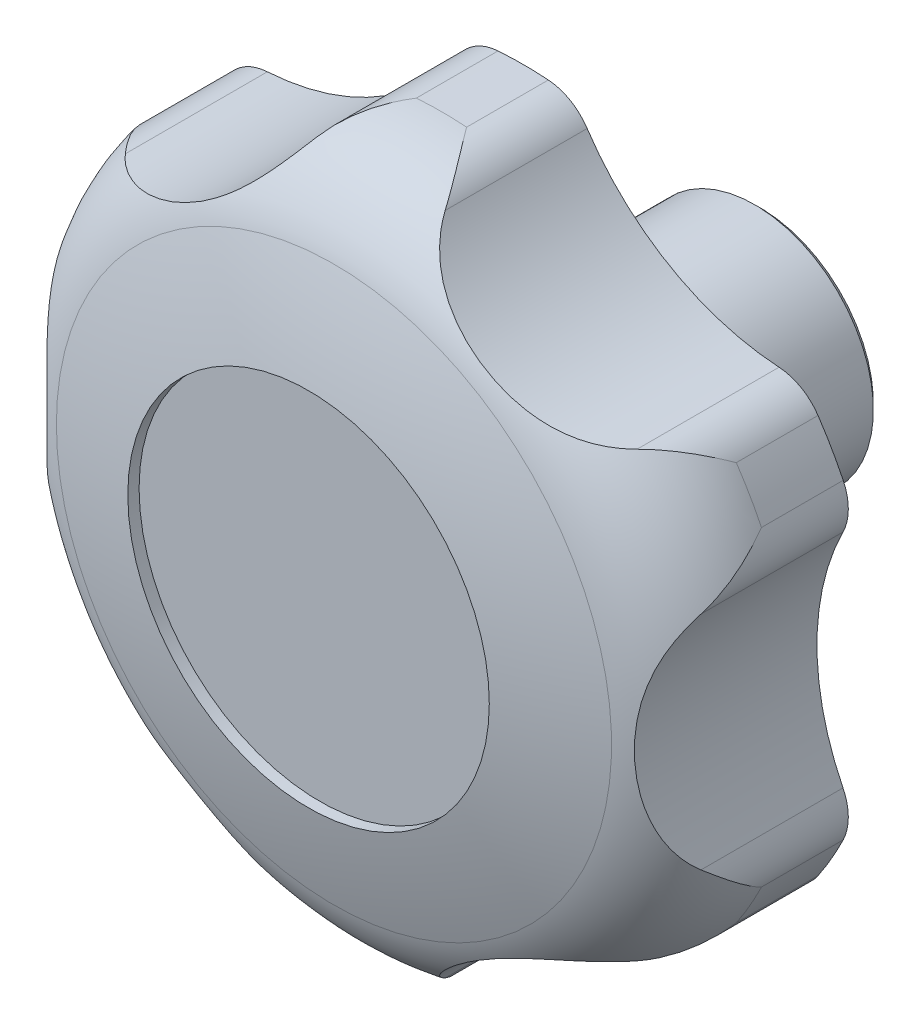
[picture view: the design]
ISO-10303-21;
HEADER;
FILE_DESCRIPTION(('STEP AP214'),'2;1');
FILE_NAME('part.step','',(''),(''),'','','');
FILE_SCHEMA(('AUTOMOTIVE_DESIGN { 1 0 10303 214 1 1 1 1 }'));
ENDSEC;
DATA;
#1=APPLICATION_CONTEXT('core data for automotive mechanical design processes');
#2=APPLICATION_PROTOCOL_DEFINITION('international standard','automotive_design',2000,#1);
#3=PRODUCT_CONTEXT('',#1,'mechanical');
#4=PRODUCT('Part','Part','',(#3));
#5=PRODUCT_RELATED_PRODUCT_CATEGORY('part','',(#4));
#6=PRODUCT_DEFINITION_FORMATION('','',#4);
#7=PRODUCT_DEFINITION_CONTEXT('part definition',#1,'design');
#8=PRODUCT_DEFINITION('design','',#6,#7);
#9=PRODUCT_DEFINITION_SHAPE('','',#8);
#10=(LENGTH_UNIT() NAMED_UNIT(*) SI_UNIT(.MILLI.,.METRE.));
#11=(NAMED_UNIT(*) PLANE_ANGLE_UNIT() SI_UNIT($,.RADIAN.));
#12=(NAMED_UNIT(*) SI_UNIT($,.STERADIAN.) SOLID_ANGLE_UNIT());
#13=UNCERTAINTY_MEASURE_WITH_UNIT(LENGTH_MEASURE(1.E-05),#10,'distance_accuracy_value','');
#14=(GEOMETRIC_REPRESENTATION_CONTEXT(3) GLOBAL_UNCERTAINTY_ASSIGNED_CONTEXT((#13)) GLOBAL_UNIT_ASSIGNED_CONTEXT((#10,
#11,#12)) REPRESENTATION_CONTEXT('',''));
#15=CARTESIAN_POINT('',(0.,0.,0.));
#16=DIRECTION('',(0.,0.,1.));
#17=DIRECTION('',(1.,0.,0.));
#18=AXIS2_PLACEMENT_3D('',#15,#16,#17);
#19=CARTESIAN_POINT('',(0.,0.,48.6287321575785));
#20=DIRECTION('',(0.,0.,1.));
#21=DIRECTION('',(-1.,0.,0.));
#22=AXIS2_PLACEMENT_3D('',#19,#20,#21);
#23=CYLINDRICAL_SURFACE('',#22,31.5);
#24=CARTESIAN_POINT('',(0.,0.,21.));
#25=DIRECTION('',(0.,0.,1.));
#26=DIRECTION('',(-1.,0.,0.));
#27=AXIS2_PLACEMENT_3D('',#24,#25,#26);
#28=CIRCLE('',#27,31.5);
#29=CARTESIAN_POINT('',(26.0979777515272,-17.639318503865,21.));
#30=VERTEX_POINT('',#29);
#31=CARTESIAN_POINT('',(28.3250868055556,-13.7818524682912,21.));
#32=VERTEX_POINT('',#31);
#33=EDGE_CURVE('E440',#30,#32,#28,.T.);
#34=ORIENTED_EDGE('',*,*,#33,.T.);
#35=DIRECTION('',(0.,0.,1.));
#36=VECTOR('',#35,1.);
#37=CARTESIAN_POINT('',(28.3250868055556,-13.7818524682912,0.));
#38=LINE('',#37,#36);
#39=CARTESIAN_POINT('',(28.3250868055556,-13.7818524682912,28.232767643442));
#40=VERTEX_POINT('',#39);
#41=EDGE_CURVE('E182',#32,#40,#38,.T.);
#42=ORIENTED_EDGE('',*,*,#41,.T.);
#43=CARTESIAN_POINT('',(0.,0.,28.232767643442));
#44=DIRECTION('',(0.,0.,1.));
#45=DIRECTION('',(-1.,0.,0.));
#46=AXIS2_PLACEMENT_3D('',#43,#44,#45);
#47=CIRCLE('',#46,31.5);
#48=CARTESIAN_POINT('',(26.0979777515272,-17.639318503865,28.232767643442));
#49=VERTEX_POINT('',#48);
#50=EDGE_CURVE('E197',#49,#40,#47,.T.);
#51=ORIENTED_EDGE('',*,*,#50,.F.);
#52=DIRECTION('',(0.,0.,1.));
#53=VECTOR('',#52,1.);
#54=CARTESIAN_POINT('',(26.0979777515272,-17.639318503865,0.));
#55=LINE('',#54,#53);
#56=EDGE_CURVE('E518',#30,#49,#55,.T.);
#57=ORIENTED_EDGE('',*,*,#56,.F.);
#58=EDGE_LOOP('',(#34,#42,#51,#57));
#59=FACE_BOUND('',#58,.T.);
#60=ADVANCED_FACE('F14',(#59),#23,.T.);
#61=CARTESIAN_POINT('',(-2.22710905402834,-31.421170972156,21.));
#62=VERTEX_POINT('',#61);
#63=CARTESIAN_POINT('',(2.22710905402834,-31.421170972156,21.));
#64=VERTEX_POINT('',#63);
#65=EDGE_CURVE('E443',#62,#64,#28,.T.);
#66=ORIENTED_EDGE('',*,*,#65,.T.);
#67=DIRECTION('',(0.,0.,1.));
#68=VECTOR('',#67,1.);
#69=CARTESIAN_POINT('',(2.22710905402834,-31.421170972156,0.));
#70=LINE('',#69,#68);
#71=CARTESIAN_POINT('',(2.22710905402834,-31.421170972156,28.232767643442));
#72=VERTEX_POINT('',#71);
#73=EDGE_CURVE('E524',#64,#72,#70,.T.);
#74=ORIENTED_EDGE('',*,*,#73,.T.);
#75=CARTESIAN_POINT('',(-2.22710905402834,-31.421170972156,28.232767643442));
#76=VERTEX_POINT('',#75);
#77=EDGE_CURVE('E454',#76,#72,#47,.T.);
#78=ORIENTED_EDGE('',*,*,#77,.F.);
#79=DIRECTION('',(0.,0.,1.));
#80=VECTOR('',#79,1.);
#81=CARTESIAN_POINT('',(-2.22710905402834,-31.421170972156,0.));
#82=LINE('',#81,#80);
#83=EDGE_CURVE('E527',#62,#76,#82,.T.);
#84=ORIENTED_EDGE('',*,*,#83,.F.);
#85=EDGE_LOOP('',(#66,#74,#78,#84));
#86=FACE_BOUND('',#85,.T.);
#87=ADVANCED_FACE('F406',(#86),#23,.T.);
#88=CARTESIAN_POINT('',(-28.3250868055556,-13.7818524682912,21.));
#89=VERTEX_POINT('',#88);
#90=CARTESIAN_POINT('',(-26.0979777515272,-17.639318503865,21.));
#91=VERTEX_POINT('',#90);
#92=EDGE_CURVE('E446',#89,#91,#28,.T.);
#93=ORIENTED_EDGE('',*,*,#92,.T.);
#94=DIRECTION('',(0.,0.,1.));
#95=VECTOR('',#94,1.);
#96=CARTESIAN_POINT('',(-26.0979777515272,-17.639318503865,0.));
#97=LINE('',#96,#95);
#98=CARTESIAN_POINT('',(-26.0979777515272,-17.639318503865,28.232767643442));
#99=VERTEX_POINT('',#98);
#100=EDGE_CURVE('E535',#91,#99,#97,.T.);
#101=ORIENTED_EDGE('',*,*,#100,.T.);
#102=CARTESIAN_POINT('',(-28.3250868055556,-13.7818524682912,28.232767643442));
#103=VERTEX_POINT('',#102);
#104=EDGE_CURVE('E450',#103,#99,#47,.T.);
#105=ORIENTED_EDGE('',*,*,#104,.F.);
#106=DIRECTION('',(0.,0.,1.));
#107=VECTOR('',#106,1.);
#108=CARTESIAN_POINT('',(-28.3250868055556,-13.7818524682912,0.));
#109=LINE('',#108,#107);
#110=EDGE_CURVE('E538',#89,#103,#109,.T.);
#111=ORIENTED_EDGE('',*,*,#110,.F.);
#112=EDGE_LOOP('',(#93,#101,#105,#111));
#113=FACE_BOUND('',#112,.T.);
#114=ADVANCED_FACE('F414',(#113),#23,.T.);
#115=CARTESIAN_POINT('',(-26.0979777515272,17.639318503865,21.));
#116=VERTEX_POINT('',#115);
#117=CARTESIAN_POINT('',(-28.3250868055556,13.7818524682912,21.));
#118=VERTEX_POINT('',#117);
#119=EDGE_CURVE('E445',#116,#118,#28,.T.);
#120=ORIENTED_EDGE('',*,*,#119,.T.);
#121=DIRECTION('',(0.,0.,1.));
#122=VECTOR('',#121,1.);
#123=CARTESIAN_POINT('',(-28.3250868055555,13.7818524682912,0.));
#124=LINE('',#123,#122);
#125=CARTESIAN_POINT('',(-28.3250868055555,13.7818524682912,28.232767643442));
#126=VERTEX_POINT('',#125);
#127=EDGE_CURVE('E37',#118,#126,#124,.T.);
#128=ORIENTED_EDGE('',*,*,#127,.T.);
#129=CARTESIAN_POINT('',(-26.0979777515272,17.639318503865,28.232767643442));
#130=VERTEX_POINT('',#129);
#131=EDGE_CURVE('E449',#130,#126,#47,.T.);
#132=ORIENTED_EDGE('',*,*,#131,.F.);
#133=DIRECTION('',(0.,0.,1.));
#134=VECTOR('',#133,1.);
#135=CARTESIAN_POINT('',(-26.0979777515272,17.639318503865,0.));
#136=LINE('',#135,#134);
#137=EDGE_CURVE('E547',#116,#130,#136,.T.);
#138=ORIENTED_EDGE('',*,*,#137,.F.);
#139=EDGE_LOOP('',(#120,#128,#132,#138));
#140=FACE_BOUND('',#139,.T.);
#141=ADVANCED_FACE('F427',(#140),#23,.T.);
#142=CARTESIAN_POINT('',(2.22710905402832,31.4211709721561,21.));
#143=VERTEX_POINT('',#142);
#144=CARTESIAN_POINT('',(-2.22710905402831,31.4211709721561,21.));
#145=VERTEX_POINT('',#144);
#146=EDGE_CURVE('E441',#143,#145,#28,.T.);
#147=ORIENTED_EDGE('',*,*,#146,.T.);
#148=DIRECTION('',(0.,0.,1.));
#149=VECTOR('',#148,1.);
#150=CARTESIAN_POINT('',(-2.22710905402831,31.4211709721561,0.));
#151=LINE('',#150,#149);
#152=CARTESIAN_POINT('',(-2.22710905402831,31.4211709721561,28.232767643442));
#153=VERTEX_POINT('',#152);
#154=EDGE_CURVE('E555',#145,#153,#151,.T.);
#155=ORIENTED_EDGE('',*,*,#154,.T.);
#156=CARTESIAN_POINT('',(2.22710905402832,31.4211709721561,28.232767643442));
#157=VERTEX_POINT('',#156);
#158=EDGE_CURVE('E571',#157,#153,#47,.T.);
#159=ORIENTED_EDGE('',*,*,#158,.F.);
#160=DIRECTION('',(0.,0.,1.));
#161=VECTOR('',#160,1.);
#162=CARTESIAN_POINT('',(2.22710905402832,31.4211709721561,0.));
#163=LINE('',#162,#161);
#164=EDGE_CURVE('E558',#143,#157,#163,.T.);
#165=ORIENTED_EDGE('',*,*,#164,.F.);
#166=EDGE_LOOP('',(#147,#155,#159,#165));
#167=FACE_BOUND('',#166,.T.);
#168=ADVANCED_FACE('F418',(#167),#23,.T.);
#169=CARTESIAN_POINT('',(28.3250868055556,13.7818524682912,21.));
#170=VERTEX_POINT('',#169);
#171=CARTESIAN_POINT('',(26.0979777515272,17.639318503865,21.));
#172=VERTEX_POINT('',#171);
#173=EDGE_CURVE('E433',#170,#172,#28,.T.);
#174=ORIENTED_EDGE('',*,*,#173,.T.);
#175=DIRECTION('',(0.,0.,1.));
#176=VECTOR('',#175,1.);
#177=CARTESIAN_POINT('',(26.0979777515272,17.639318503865,0.));
#178=LINE('',#177,#176);
#179=CARTESIAN_POINT('',(26.0979777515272,17.639318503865,28.232767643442));
#180=VERTEX_POINT('',#179);
#181=EDGE_CURVE('E435',#172,#180,#178,.T.);
#182=ORIENTED_EDGE('',*,*,#181,.T.);
#183=CARTESIAN_POINT('',(28.3250868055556,13.7818524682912,28.232767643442));
#184=VERTEX_POINT('',#183);
#185=EDGE_CURVE('E570',#184,#180,#47,.T.);
#186=ORIENTED_EDGE('',*,*,#185,.F.);
#187=DIRECTION('',(0.,0.,1.));
#188=VECTOR('',#187,1.);
#189=CARTESIAN_POINT('',(28.3250868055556,13.7818524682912,0.));
#190=LINE('',#189,#188);
#191=EDGE_CURVE('E437',#170,#184,#190,.T.);
#192=ORIENTED_EDGE('',*,*,#191,.F.);
#193=EDGE_LOOP('',(#174,#182,#186,#192));
#194=FACE_BOUND('',#193,.T.);
#195=ADVANCED_FACE('F408',(#194),#23,.T.);
#196=CARTESIAN_POINT('',(0.,0.,48.6287321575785));
#197=DIRECTION('',(0.,0.,1.));
#198=DIRECTION('',(-1.,0.,0.));
#199=AXIS2_PLACEMENT_3D('',#196,#197,#198);
#200=CYLINDRICAL_SURFACE('',#199,13.);
#201=CARTESIAN_POINT('',(0.,0.,21.));
#202=DIRECTION('',(0.,0.,1.));
#203=DIRECTION('',(-1.,0.,0.));
#204=AXIS2_PLACEMENT_3D('',#201,#202,#203);
#205=CIRCLE('',#204,13.);
#206=CARTESIAN_POINT('',(-13.,0.,21.));
#207=VERTEX_POINT('',#206);
#208=EDGE_CURVE('E469',#207,#207,#205,.T.);
#209=ORIENTED_EDGE('',*,*,#208,.F.);
#210=EDGE_LOOP('',(#209));
#211=FACE_BOUND('',#210,.T.);
#212=CARTESIAN_POINT('',(0.,0.,19.));
#213=DIRECTION('',(0.,0.,1.));
#214=DIRECTION('',(-1.,0.,0.));
#215=AXIS2_PLACEMENT_3D('',#212,#213,#214);
#216=CIRCLE('',#215,13.);
#217=CARTESIAN_POINT('',(-13.,0.,19.));
#218=VERTEX_POINT('',#217);
#219=EDGE_CURVE('E466',#218,#218,#216,.T.);
#220=ORIENTED_EDGE('',*,*,#219,.T.);
#221=EDGE_LOOP('',(#220));
#222=FACE_BOUND('',#221,.T.);
#223=ADVANCED_FACE('F16',(#211,#222),#200,.T.);
#224=CARTESIAN_POINT('',(0.,10.5,19.));
#225=DIRECTION('',(0.,0.,1.));
#226=DIRECTION('',(-1.,0.,0.));
#227=AXIS2_PLACEMENT_3D('',#224,#225,#226);
#228=PLANE('',#227);
#229=ORIENTED_EDGE('',*,*,#219,.F.);
#230=EDGE_LOOP('',(#229));
#231=FACE_BOUND('',#230,.T.);
#232=CARTESIAN_POINT('',(0.,0.,19.));
#233=DIRECTION('',(0.,0.,1.));
#234=DIRECTION('',(-1.,0.,0.));
#235=AXIS2_PLACEMENT_3D('',#232,#233,#234);
#236=CIRCLE('',#235,10.5);
#237=CARTESIAN_POINT('',(-10.5,0.,19.));
#238=VERTEX_POINT('',#237);
#239=EDGE_CURVE('E463',#238,#238,#236,.T.);
#240=ORIENTED_EDGE('',*,*,#239,.T.);
#241=EDGE_LOOP('',(#240));
#242=FACE_BOUND('',#241,.T.);
#243=ADVANCED_FACE('F425',(#231,#242),#228,.F.);
#244=CARTESIAN_POINT('',(0.,0.,48.6287321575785));
#245=DIRECTION('',(0.,0.,1.));
#246=DIRECTION('',(-1.,0.,0.));
#247=AXIS2_PLACEMENT_3D('',#244,#245,#246);
#248=CYLINDRICAL_SURFACE('',#247,10.5);
#249=CARTESIAN_POINT('',(0.,0.,0.5));
#250=DIRECTION('',(0.,0.,1.));
#251=DIRECTION('',(-1.,0.,0.));
#252=AXIS2_PLACEMENT_3D('',#249,#250,#251);
#253=CIRCLE('',#252,10.5);
#254=CARTESIAN_POINT('',(-10.5,0.,0.5));
#255=VERTEX_POINT('',#254);
#256=EDGE_CURVE('E460',#255,#255,#253,.T.);
#257=ORIENTED_EDGE('',*,*,#256,.T.);
#258=EDGE_LOOP('',(#257));
#259=FACE_BOUND('',#258,.T.);
#260=ORIENTED_EDGE('',*,*,#239,.F.);
#261=EDGE_LOOP('',(#260));
#262=FACE_BOUND('',#261,.T.);
#263=ADVANCED_FACE('F604',(#259,#262),#248,.T.);
#264=CARTESIAN_POINT('',(0.,0.,0.));
#265=DIRECTION('',(0.,0.,1.));
#266=DIRECTION('',(-1.,0.,0.));
#267=AXIS2_PLACEMENT_3D('',#264,#265,#266);
#268=CONICAL_SURFACE('',#267,10.,0.785398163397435);
#269=ORIENTED_EDGE('',*,*,#256,.F.);
#270=EDGE_LOOP('',(#269));
#271=FACE_BOUND('',#270,.T.);
#272=CARTESIAN_POINT('',(0.,0.,0.));
#273=DIRECTION('',(0.,0.,1.));
#274=DIRECTION('',(-1.,0.,0.));
#275=AXIS2_PLACEMENT_3D('',#272,#273,#274);
#276=CIRCLE('',#275,10.);
#277=CARTESIAN_POINT('',(-10.,0.,0.));
#278=VERTEX_POINT('',#277);
#279=EDGE_CURVE('E457',#278,#278,#276,.T.);
#280=ORIENTED_EDGE('',*,*,#279,.T.);
#281=EDGE_LOOP('',(#280));
#282=FACE_BOUND('',#281,.T.);
#283=ADVANCED_FACE('F598',(#271,#282),#268,.T.);
#284=CARTESIAN_POINT('',(0.,0.,0.));
#285=DIRECTION('',(0.,0.,1.));
#286=DIRECTION('',(-1.,0.,0.));
#287=AXIS2_PLACEMENT_3D('',#284,#285,#286);
#288=PLANE('',#287);
#289=ORIENTED_EDGE('',*,*,#279,.F.);
#290=EDGE_LOOP('',(#289));
#291=FACE_BOUND('',#290,.T.);
#292=ADVANCED_FACE('F591',(#291),#288,.F.);
#293=CARTESIAN_POINT('',(0.,0.,-38.3836717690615));
#294=DIRECTION('',(-1.,0.,0.));
#295=DIRECTION('',(0.,0.,-1.));
#296=AXIS2_PLACEMENT_3D('',#293,#294,#295);
#297=SPHERICAL_SURFACE('',#296,79.9999999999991);
#298=CARTESIAN_POINT('',(0.,0.,-38.3836717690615));
#299=DIRECTION('',(0.,0.,1.));
#300=DIRECTION('',(-1.,0.,0.));
#301=AXIS2_PLACEMENT_3D('',#298,#299,#300);
#302=SPHERICAL_SURFACE('',#301,79.9999999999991);
#303=CARTESIAN_POINT('',(0.,0.,37.7494018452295));
#304=DIRECTION('',(0.,0.,1.));
#305=DIRECTION('',(-1.,0.,0.));
#306=AXIS2_PLACEMENT_3D('',#303,#304,#305);
#307=CIRCLE('',#306,24.5714285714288);
#308=CARTESIAN_POINT('',(-24.5714285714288,0.,37.7494018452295));
#309=VERTEX_POINT('',#308);
#310=EDGE_CURVE('E453',#309,#309,#307,.T.);
#311=ORIENTED_EDGE('',*,*,#310,.T.);
#312=EDGE_LOOP('',(#311));
#313=FACE_BOUND('',#312,.T.);
#314=CARTESIAN_POINT('',(0.,0.,40.));
#315=DIRECTION('',(0.,0.,1.));
#316=DIRECTION('',(-1.,0.,0.));
#317=AXIS2_PLACEMENT_3D('',#314,#315,#316);
#318=CIRCLE('',#317,16.);
#319=CARTESIAN_POINT('',(-16.,0.,40.));
#320=VERTEX_POINT('',#319);
#321=EDGE_CURVE('E198',#320,#320,#318,.T.);
#322=ORIENTED_EDGE('',*,*,#321,.F.);
#323=EDGE_LOOP('',(#322));
#324=FACE_BOUND('',#323,.T.);
#325=ADVANCED_FACE('F589',(#313,#324),#302,.T.);
#326=CARTESIAN_POINT('',(0.,0.,28.232767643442));
#327=DIRECTION('',(0.,0.,1.));
#328=DIRECTION('',(-1.,0.,0.));
#329=AXIS2_PLACEMENT_3D('',#326,#327,#328);
#330=TOROIDAL_SURFACE('',#329,21.5,10.);
#331=CARTESIAN_POINT('',(26.0979777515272,-17.639318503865,28.232767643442));
#332=CARTESIAN_POINT('',(26.0957873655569,-17.6425592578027,28.2381661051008));
#333=CARTESIAN_POINT('',(26.0935927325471,-17.6457971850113,28.2435646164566));
#334=CARTESIAN_POINT('',(25.9715048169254,-17.8254189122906,28.5433082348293));
#335=CARTESIAN_POINT('',(25.8390070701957,-17.9933768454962,28.8377892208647));
#336=CARTESIAN_POINT('',(25.5505586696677,-18.3097082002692,29.4258443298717));
#337=CARTESIAN_POINT('',(25.3945993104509,-18.4580743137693,29.7194180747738));
#338=CARTESIAN_POINT('',(25.060613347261,-18.7326906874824,30.3051183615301));
#339=CARTESIAN_POINT('',(24.8825534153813,-18.8589068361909,30.5972420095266));
#340=CARTESIAN_POINT('',(24.5064415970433,-19.085843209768,31.1782260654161));
#341=CARTESIAN_POINT('',(24.3084021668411,-19.1865791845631,31.4670883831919));
#342=CARTESIAN_POINT('',(23.8777210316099,-19.3661170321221,32.0631220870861));
#343=CARTESIAN_POINT('',(23.643582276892,-19.4425638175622,32.3699417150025));
#344=CARTESIAN_POINT('',(23.2789979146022,-19.5283534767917,32.8243186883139));
#345=CARTESIAN_POINT('',(23.1553286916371,-19.5521302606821,32.9747024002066));
#346=CARTESIAN_POINT('',(22.9038337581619,-19.5894090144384,33.2733876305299));
#347=CARTESIAN_POINT('',(22.7760057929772,-19.6029053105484,33.4216879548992));
#348=CARTESIAN_POINT('',(22.6463394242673,-19.610904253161,33.5687610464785));
#349=B_SPLINE_CURVE_WITH_KNOTS('',3,(#331,#332,#333,#334,#335,#336,#337,#338,#339,#340,#341,
#342,#343,#344,#345,#346,#347,#348),.UNSPECIFIED.,.F.,.F.,(4,2,2,2,2,2,2,2,4),(0.,
0.0200000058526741,1.11045859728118,2.20132280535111,3.29385250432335,4.3857052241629,
5.56362960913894,6.15179569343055,6.74028614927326),.UNSPECIFIED.);
#350=CARTESIAN_POINT('',(22.6465394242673,-19.610891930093,33.568534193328));
#351=VERTEX_POINT('',#350);
#352=EDGE_CURVE('E199',#49,#351,#349,.T.);
#353=ORIENTED_EDGE('',*,*,#352,.F.);
#354=ORIENTED_EDGE('',*,*,#50,.T.);
#355=CARTESIAN_POINT('',(28.3067007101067,-9.8068324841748,33.568787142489));
#356=CARTESIAN_POINT('',(28.3508912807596,-9.89556849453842,33.4565618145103));
#357=CARTESIAN_POINT('',(28.3917729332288,-9.98498886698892,33.3436125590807));
#358=CARTESIAN_POINT('',(28.4670914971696,-10.1648549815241,33.1164224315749));
#359=CARTESIAN_POINT('',(28.5015295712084,-10.2553005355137,33.0021817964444));
#360=CARTESIAN_POINT('',(28.5953953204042,-10.5275208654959,32.6579333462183));
#361=CARTESIAN_POINT('',(28.6454651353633,-10.7103641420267,32.426166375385));
#362=CARTESIAN_POINT('',(28.721810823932,-11.076055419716,31.9595965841));
#363=CARTESIAN_POINT('',(28.7481337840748,-11.2589026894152,31.7248007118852));
#364=CARTESIAN_POINT('',(28.7783405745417,-11.622978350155,31.2525284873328));
#365=CARTESIAN_POINT('',(28.7822209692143,-11.804206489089,31.0150517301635));
#366=CARTESIAN_POINT('',(28.7634739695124,-12.2980890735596,30.3589883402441));
#367=CARTESIAN_POINT('',(28.7187582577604,-12.607264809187,29.9382841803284));
#368=CARTESIAN_POINT('',(28.5687108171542,-13.206004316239,29.0945771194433));
#369=CARTESIAN_POINT('',(28.4634632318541,-13.4955946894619,28.6715782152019));
#370=CARTESIAN_POINT('',(28.3285049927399,-13.7748156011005,28.2435645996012));
#371=CARTESIAN_POINT('',(28.3267981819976,-13.7783351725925,28.2381660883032));
#372=CARTESIAN_POINT('',(28.3250868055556,-13.7818524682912,28.232767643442));
#373=B_SPLINE_CURVE_WITH_KNOTS('',3,(#355,#356,#357,#358,#359,#360,#361,#362,#363,#364,#365,
#366,#367,#368,#369,#370,#371,#372),.UNSPECIFIED.,.F.,.F.,(4,2,2,2,2,2,2,2,4),(0.,
0.449123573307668,0.89816603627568,1.79532231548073,2.69069573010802,3.58620621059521,
5.15403517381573,6.71968999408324,6.73968999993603),.UNSPECIFIED.);
#374=CARTESIAN_POINT('',(28.3068003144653,-9.8070324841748,33.568534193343));
#375=VERTEX_POINT('',#374);
#376=EDGE_CURVE('E186',#375,#40,#373,.T.);
#377=ORIENTED_EDGE('',*,*,#376,.F.);
#378=CARTESIAN_POINT('',(28.306899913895,-9.80723248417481,33.568281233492));
#379=CARTESIAN_POINT('',(28.2673881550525,-9.72789258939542,33.6686385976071));
#380=CARTESIAN_POINT('',(28.227286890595,-9.64616596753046,33.7668454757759));
#381=CARTESIAN_POINT('',(28.1461835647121,-9.47811588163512,33.9588369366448));
#382=CARTESIAN_POINT('',(28.1051815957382,-9.39179288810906,34.0526219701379));
#383=CARTESIAN_POINT('',(27.9813412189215,-9.12640847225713,34.3269450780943));
#384=CARTESIAN_POINT('',(27.8975600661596,-8.94071625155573,34.5007229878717));
#385=CARTESIAN_POINT('',(27.7306770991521,-8.55559108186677,34.8277600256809));
#386=CARTESIAN_POINT('',(27.6475773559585,-8.35632234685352,34.9812149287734));
#387=CARTESIAN_POINT('',(27.4831867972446,-7.94415498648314,35.2697558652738));
#388=CARTESIAN_POINT('',(27.4018963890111,-7.73125333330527,35.4048377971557));
#389=CARTESIAN_POINT('',(27.2432790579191,-7.29467382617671,35.656528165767));
#390=CARTESIAN_POINT('',(27.1659377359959,-7.07104190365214,35.7732075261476));
#391=CARTESIAN_POINT('',(27.0164001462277,-6.61410095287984,35.9895642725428));
#392=CARTESIAN_POINT('',(26.9442035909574,-6.38079246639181,36.0892426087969));
#393=CARTESIAN_POINT('',(26.8060036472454,-5.90558258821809,36.2729593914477));
#394=CARTESIAN_POINT('',(26.7400171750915,-5.66366006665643,36.3569556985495));
#395=CARTESIAN_POINT('',(26.6154160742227,-5.173356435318,36.510259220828));
#396=CARTESIAN_POINT('',(26.5568025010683,-4.92497440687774,36.5795643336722));
#397=CARTESIAN_POINT('',(26.4181661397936,-4.28729101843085,36.738696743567));
#398=CARTESIAN_POINT('',(26.3437188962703,-3.89445767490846,36.8193385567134));
#399=CARTESIAN_POINT('',(26.2158958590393,-3.10074997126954,36.9533643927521));
#400=CARTESIAN_POINT('',(26.1625301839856,-2.69987184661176,37.006735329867));
#401=CARTESIAN_POINT('',(26.0777773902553,-1.89243908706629,37.0898241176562));
#402=CARTESIAN_POINT('',(26.0464425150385,-1.48587327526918,37.1194857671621));
#403=CARTESIAN_POINT('',(26.0064401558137,-0.670716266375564,37.1571359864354));
#404=CARTESIAN_POINT('',(25.9977694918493,-0.262125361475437,37.1651275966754));
#405=CARTESIAN_POINT('',(26.0032673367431,0.564334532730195,37.1600141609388));
#406=CARTESIAN_POINT('',(26.01797448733,0.982197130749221,37.146411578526));
#407=CARTESIAN_POINT('',(26.0710365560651,1.81513174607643,37.0960704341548));
#408=CARTESIAN_POINT('',(26.1093958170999,2.23020323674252,37.0593276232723));
#409=CARTESIAN_POINT('',(26.2090070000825,3.05355191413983,36.9600301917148));
#410=CARTESIAN_POINT('',(26.2702065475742,3.46184242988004,36.8975345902));
#411=CARTESIAN_POINT('',(26.4142334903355,4.26876333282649,36.7425858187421));
#412=CARTESIAN_POINT('',(26.4970492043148,4.66739881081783,36.6501488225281));
#413=CARTESIAN_POINT('',(26.65189721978,5.32280567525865,36.4661289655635));
#414=CARTESIAN_POINT('',(26.7186645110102,5.58351647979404,36.3840627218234));
#415=CARTESIAN_POINT('',(26.8599386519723,6.09659869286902,36.2024669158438));
#416=CARTESIAN_POINT('',(26.9344431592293,6.34897259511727,36.1029426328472));
#417=CARTESIAN_POINT('',(27.0896194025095,6.84271708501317,35.8852972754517));
#418=CARTESIAN_POINT('',(27.1702731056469,7.08411676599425,35.7672295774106));
#419=CARTESIAN_POINT('',(27.336207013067,7.55445583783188,35.5111726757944));
#420=CARTESIAN_POINT('',(27.4214863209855,7.78339762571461,35.3731873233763));
#421=CARTESIAN_POINT('',(27.5743147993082,8.17463300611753,35.1113840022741));
#422=CARTESIAN_POINT('',(27.6413411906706,8.33998254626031,34.9918111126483));
#423=CARTESIAN_POINT('',(27.7758194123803,8.66099232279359,34.7405668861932));
#424=CARTESIAN_POINT('',(27.8432711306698,8.81665500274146,34.6088986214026));
#425=CARTESIAN_POINT('',(27.9779423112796,9.11836971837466,34.3326466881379));
#426=CARTESIAN_POINT('',(28.0451570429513,9.26434887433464,34.1879809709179));
#427=CARTESIAN_POINT('',(28.177732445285,9.54473083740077,33.8868532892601));
#428=CARTESIAN_POINT('',(28.2430918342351,9.67912576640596,33.730383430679));
#429=CARTESIAN_POINT('',(28.306899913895,9.807232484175,33.5682812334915));
#430=B_SPLINE_CURVE_WITH_KNOTS('',3,(#378,#379,#380,#381,#382,#383,#384,#385,#386,#387,#388,
#389,#390,#391,#392,#393,#394,#395,#396,#397,#398,#399,#400,#401,#402,#403,#404,#405,#406,#407,
#408,#409,#410,#411,#412,#413,#414,#415,#416,#417,#418,#419,#420,#421,#422,#423,#424,#425,#426,
#427,#428,#429),.UNSPECIFIED.,.F.,.F.,(4,2,2,2,2,2,2,2,2,2,2,2,2,2,2,2,2,2,2,2,2,2,2,2,2,4),(0.,
0.401597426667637,0.803153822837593,1.60518118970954,2.39881165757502,3.19261900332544,
3.98328802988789,4.77391284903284,5.56663251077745,6.35946553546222,7.58127502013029,
8.8036702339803,10.028954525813,11.2540668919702,12.5078182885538,13.7617999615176,
15.0129236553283,16.2633726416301,17.106781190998,17.9499351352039,18.7907051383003,
19.6313127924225,20.2751395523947,20.9188032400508,21.5668619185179,22.2153579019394),.UNSPECIFIED.);
#431=CARTESIAN_POINT('',(28.3068003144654,9.80703248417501,33.5685341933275));
#432=VERTEX_POINT('',#431);
#433=EDGE_CURVE('E174',#375,#432,#430,.T.);
#434=ORIENTED_EDGE('',*,*,#433,.T.);
#435=CARTESIAN_POINT('',(28.3250868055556,13.7818524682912,28.232767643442));
#436=CARTESIAN_POINT('',(28.3267981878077,13.7783351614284,28.2381661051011));
#437=CARTESIAN_POINT('',(28.3285049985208,13.774815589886,28.2435646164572));
#438=CARTESIAN_POINT('',(28.4230180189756,13.5792734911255,28.5433082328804));
#439=CARTESIAN_POINT('',(28.5022249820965,13.3805481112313,28.8377892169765));
#440=CARTESIAN_POINT('',(28.6319517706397,12.9725787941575,29.4258443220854));
#441=CARTESIAN_POINT('',(28.6824609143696,12.7633309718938,29.7194180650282));
#442=CARTESIAN_POINT('',(28.7532926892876,12.3367824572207,30.3051183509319));
#443=CARTESIAN_POINT('',(28.7735691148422,12.1194699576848,30.5972420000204));
#444=CARTESIAN_POINT('',(28.7820458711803,11.6802793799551,31.1782260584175));
#445=CARTESIAN_POINT('',(28.7702660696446,11.4584042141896,31.467088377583));
#446=CARTESIAN_POINT('',(28.7104093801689,10.9956509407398,32.0631266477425));
#447=CARTESIAN_POINT('',(28.6595438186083,10.7546538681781,32.3699507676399));
#448=CARTESIAN_POINT('',(28.5515451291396,10.3960144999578,32.8243342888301));
#449=CARTESIAN_POINT('',(28.5103008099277,10.2770236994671,32.9747201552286));
#450=CARTESIAN_POINT('',(28.416835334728,10.0405799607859,33.2734096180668));
#451=CARTESIAN_POINT('',(28.3646081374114,9.92312790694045,33.4217120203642));
#452=CARTESIAN_POINT('',(28.3067007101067,9.80683248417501,33.568787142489));
#453=B_SPLINE_CURVE_WITH_KNOTS('',3,(#435,#436,#437,#438,#439,#440,#441,#442,#443,#444,#445,
#446,#447,#448,#449,#450,#451,#452),.UNSPECIFIED.,.F.,.F.,(4,2,2,2,2,2,2,2,4),(0.,
0.020000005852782,1.1104585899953,2.20132279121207,3.29385249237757,4.38570522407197,
5.56364696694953,6.15182175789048,6.74032093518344),.UNSPECIFIED.);
#454=EDGE_CURVE('E181',#184,#432,#453,.T.);
#455=ORIENTED_EDGE('',*,*,#454,.F.);
#456=ORIENTED_EDGE('',*,*,#185,.T.);
#457=CARTESIAN_POINT('',(22.6463394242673,19.610904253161,33.5687610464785));
#458=CARTESIAN_POINT('',(22.7452824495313,19.6048058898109,33.4565353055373));
#459=CARTESIAN_POINT('',(22.8431636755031,19.5954997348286,33.3435856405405));
#460=CARTESIAN_POINT('',(23.036591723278,19.5707934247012,33.11639470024));
#461=CARTESIAN_POINT('',(23.132138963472,19.5553943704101,33.0021536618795));
#462=CARTESIAN_POINT('',(23.4148216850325,19.5005727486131,32.6579040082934));
#463=CARTESIAN_POINT('',(23.5982035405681,19.4525117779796,32.4261362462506));
#464=CARTESIAN_POINT('',(23.953074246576,19.3357813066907,31.9595649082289));
#465=CARTESIAN_POINT('',(24.1245860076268,19.2671529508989,31.7247682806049));
#466=CARTESIAN_POINT('',(24.4549878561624,19.1112728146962,31.2524945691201));
#467=CARTESIAN_POINT('',(24.613876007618,19.0240181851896,31.015017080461));
#468=CARTESIAN_POINT('',(25.0322121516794,18.7608413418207,30.3589586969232));
#469=CARTESIAN_POINT('',(25.2776039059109,18.5675303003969,29.938260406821));
#470=CARTESIAN_POINT('',(25.7210962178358,18.138220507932,29.0945651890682));
#471=CARTESIAN_POINT('',(25.9192618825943,17.9022813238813,28.6715722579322));
#472=CARTESIAN_POINT('',(26.0935927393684,17.6457971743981,28.2435645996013));
#473=CARTESIAN_POINT('',(26.09578737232,17.6425592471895,28.2381660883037));
#474=CARTESIAN_POINT('',(26.0979777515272,17.639318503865,28.232767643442));
#475=B_SPLINE_CURVE_WITH_KNOTS('',3,(#457,#458,#459,#460,#461,#462,#463,#464,#465,#466,#467,
#468,#469,#470,#471,#472,#473,#474),.UNSPECIFIED.,.F.,.F.,(4,2,2,2,2,2,2,2,4),(0.,
0.449124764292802,0.898168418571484,1.79532709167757,2.6907028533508,3.58621567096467,
5.15402250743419,6.71965525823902,6.73965526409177),.UNSPECIFIED.);
#476=CARTESIAN_POINT('',(22.6465394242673,19.610891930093,33.5685341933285));
#477=VERTEX_POINT('',#476);
#478=EDGE_CURVE('E246',#477,#180,#475,.T.);
#479=ORIENTED_EDGE('',*,*,#478,.F.);
#480=CARTESIAN_POINT('',(22.6467394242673,19.6108796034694,33.568307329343));
#481=CARTESIAN_POINT('',(22.5582725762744,19.6163314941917,33.6686645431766));
#482=CARTESIAN_POINT('',(22.4674440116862,19.622466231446,33.7668712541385));
#483=CARTESIAN_POINT('',(22.2813555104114,19.6362540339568,33.9588623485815));
#484=CARTESIAN_POINT('',(22.1860960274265,19.6439069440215,34.0526471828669));
#485=CARTESIAN_POINT('',(21.8943444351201,19.6693507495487,34.3269696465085));
#486=CARTESIAN_POINT('',(21.6916385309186,19.689640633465,34.5007470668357));
#487=CARTESIAN_POINT('',(21.2746666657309,19.737679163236,34.8277830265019));
#488=CARTESIAN_POINT('',(21.0605439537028,19.7653474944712,34.9812373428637));
#489=CARTESIAN_POINT('',(20.6213992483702,19.8290657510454,35.2697770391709));
#490=CARTESIAN_POINT('',(20.396374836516,19.8651175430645,35.4048583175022));
#491=CARTESIAN_POINT('',(19.938975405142,19.9460417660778,35.6565473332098));
#492=CARTESIAN_POINT('',(19.7066329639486,19.990878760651,35.7732259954));
#493=CARTESIAN_POINT('',(19.2361400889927,20.089847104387,35.9895813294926));
#494=CARTESIAN_POINT('',(18.9979899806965,20.1439779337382,36.0892589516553));
#495=CARTESIAN_POINT('',(18.5173447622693,20.2618995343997,36.2729743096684));
#496=CARTESIAN_POINT('',(18.2748398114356,20.3257155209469,36.356969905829));
#497=CARTESIAN_POINT('',(17.7879226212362,20.4629610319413,36.5102720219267));
#498=CARTESIAN_POINT('',(17.5435101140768,20.5363919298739,36.5795764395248));
#499=CARTESIAN_POINT('',(16.9219401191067,20.7351730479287,36.7387072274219));
#500=CARTESIAN_POINT('',(16.5445116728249,20.8671178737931,36.8193480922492));
#501=CARTESIAN_POINT('',(15.7932269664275,21.1532765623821,36.9533720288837));
#502=CARTESIAN_POINT('',(15.4193725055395,21.3075010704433,37.0067420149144));
#503=CARTESIAN_POINT('',(14.6777370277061,21.6378224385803,37.0898288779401));
#504=CARTESIAN_POINT('',(14.3099724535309,21.8139701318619,37.1194895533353));
#505=CARTESIAN_POINT('',(13.5840231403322,22.1869088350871,37.1571377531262));
#506=CARTESIAN_POINT('',(13.2258370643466,22.3836969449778,37.1651283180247));
#507=CARTESIAN_POINT('',(12.5128497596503,22.8016915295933,37.1600126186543));
#508=CARTESIAN_POINT('',(12.1583233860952,23.0233612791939,37.146408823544));
#509=CARTESIAN_POINT('',(11.4635114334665,23.4857850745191,37.0960650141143));
#510=CARTESIAN_POINT('',(11.1232284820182,23.7265426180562,37.0593207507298));
#511=CARTESIAN_POINT('',(10.4599932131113,24.2244861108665,36.9600200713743));
#512=CARTESIAN_POINT('',(10.1370031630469,24.4816333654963,36.8975226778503));
#513=CARTESIAN_POINT('',(9.51020318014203,25.0098279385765,36.7425698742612));
#514=CARTESIAN_POINT('',(9.20638299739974,25.2808676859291,36.6501306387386));
#515=CARTESIAN_POINT('',(8.71621052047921,25.7426742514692,36.466107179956));
#516=CARTESIAN_POINT('',(8.52381391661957,25.9308511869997,36.384039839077));
#517=CARTESIAN_POINT('',(8.15011259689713,26.3097378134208,36.202441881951));
#518=CARTESIAN_POINT('',(7.96880455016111,26.5004467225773,36.1029165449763));
#519=CARTESIAN_POINT('',(7.6188011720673,26.8817036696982,35.8852691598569));
#520=CARTESIAN_POINT('',(7.45007162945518,27.072250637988,35.7672004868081));
#521=CARTESIAN_POINT('',(7.12571667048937,27.4511209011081,35.5111417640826));
#522=CARTESIAN_POINT('',(6.97008873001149,27.6394446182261,35.3731555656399));
#523=CARTESIAN_POINT('',(6.70768734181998,27.9674120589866,35.1113519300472));
#524=CARTESIAN_POINT('',(6.59800591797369,28.1081310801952,34.9917796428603));
#525=CARTESIAN_POINT('',(6.38724675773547,28.3850929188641,34.7405369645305));
#526=CARTESIAN_POINT('',(6.28616684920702,28.521336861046,34.6088696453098));
#527=CARTESIAN_POINT('',(6.09221377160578,28.7888183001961,34.3326200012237));
#528=CARTESIAN_POINT('',(5.99940134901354,28.9200152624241,34.1879556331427));
#529=CARTESIAN_POINT('',(5.82287463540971,29.1750154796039,33.886831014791));
#530=CARTESIAN_POINT('',(5.73916652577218,29.2988136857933,33.7303628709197));
#531=CARTESIAN_POINT('',(5.66012837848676,29.4181244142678,33.5682625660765));
#532=B_SPLINE_CURVE_WITH_KNOTS('',3,(#480,#481,#482,#483,#484,#485,#486,#487,#488,#489,#490,
#491,#492,#493,#494,#495,#496,#497,#498,#499,#500,#501,#502,#503,#504,#505,#506,#507,#508,#509,
#510,#511,#512,#513,#514,#515,#516,#517,#518,#519,#520,#521,#522,#523,#524,#525,#526,#527,#528,
#529,#530,#531),.UNSPECIFIED.,.F.,.F.,(4,2,2,2,2,2,2,2,2,2,2,2,2,2,2,2,2,2,2,2,2,2,2,2,2,4),(0.,
0.401598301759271,0.80315557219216,1.60518467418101,2.39881681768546,3.19262584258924,
3.98329649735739,4.7739229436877,5.56664425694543,6.35947893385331,7.58129241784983,
8.80369163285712,10.0289799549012,11.2540963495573,12.507851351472,13.7618366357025,
15.0129638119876,16.2634162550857,17.1068205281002,17.9499701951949,18.7907359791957,
19.6313394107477,20.2751571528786,20.9188118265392,21.5668612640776,22.2153479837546),.UNSPECIFIED.);
#533=CARTESIAN_POINT('',(5.66026089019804,29.4179244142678,33.5685341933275));
#534=VERTEX_POINT('',#533);
#535=EDGE_CURVE('E252',#477,#534,#532,.T.);
#536=ORIENTED_EDGE('',*,*,#535,.T.);
#537=CARTESIAN_POINT('',(2.22710905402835,31.4211709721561,28.232767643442));
#538=CARTESIAN_POINT('',(2.23101082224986,31.4208944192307,28.2381661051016));
#539=CARTESIAN_POINT('',(2.23491226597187,31.4206127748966,28.2435646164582));
#540=CARTESIAN_POINT('',(2.45151320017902,31.4046924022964,28.5433082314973));
#541=CARTESIAN_POINT('',(2.66321790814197,31.3739249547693,28.8377892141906));
#542=CARTESIAN_POINT('',(3.08139309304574,31.2822869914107,29.4258443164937));
#543=CARTESIAN_POINT('',(3.28786159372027,31.2214052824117,29.7194180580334));
#544=CARTESIAN_POINT('',(3.69267933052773,31.0694731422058,30.3051183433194));
#545=CARTESIAN_POINT('',(3.89101568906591,30.9783767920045,30.5972419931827));
#546=CARTESIAN_POINT('',(4.27560426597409,30.7661225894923,31.1782260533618));
#547=CARTESIAN_POINT('',(4.46186389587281,30.6449833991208,31.467088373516));
#548=CARTESIAN_POINT('',(4.8326936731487,30.3617677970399,32.0631299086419));
#549=CARTESIAN_POINT('',(5.01597231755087,30.1972164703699,32.3699572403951));
#550=CARTESIAN_POINT('',(5.27256610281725,29.9243637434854,32.824345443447));
#551=CARTESIAN_POINT('',(5.35499370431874,29.8291484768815,32.9747328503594));
#552=CARTESIAN_POINT('',(5.51302848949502,29.6299804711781,33.2734253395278));
#553=CARTESIAN_POINT('',(5.58863188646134,29.5260229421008,33.4217292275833));
#554=CARTESIAN_POINT('',(5.6603933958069,29.4177244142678,33.5688058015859));
#555=B_SPLINE_CURVE_WITH_KNOTS('',3,(#537,#538,#539,#540,#541,#542,#543,#544,#545,#546,#547,
#548,#549,#550,#551,#552,#553,#554),.UNSPECIFIED.,.F.,.F.,(4,2,2,2,2,2,2,2,4),(0.,
0.0200000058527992,1.11045858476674,2.20132278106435,3.29385248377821,4.38570522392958,
5.56365937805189,6.15184039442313,6.74034580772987),.UNSPECIFIED.);
#556=EDGE_CURVE('E275',#157,#534,#555,.T.);
#557=ORIENTED_EDGE('',*,*,#556,.F.);
#558=ORIENTED_EDGE('',*,*,#158,.T.);
#559=CARTESIAN_POINT('',(-5.6603933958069,29.4177244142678,33.5688058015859));
#560=CARTESIAN_POINT('',(-5.60564139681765,29.5003626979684,33.456580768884));
#561=CARTESIAN_POINT('',(-5.54864226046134,29.5804775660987,33.3436318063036));
#562=CARTESIAN_POINT('',(-5.43053361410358,29.7356386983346,33.1164422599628));
#563=CARTESIAN_POINT('',(-5.3694248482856,29.810685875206,33.0022019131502));
#564=CARTESIAN_POINT('',(-5.18060902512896,30.028086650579,32.6579543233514));
#565=CARTESIAN_POINT('',(-5.04729767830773,30.1628703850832,32.4261879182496));
#566=CARTESIAN_POINT('',(-4.76877388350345,30.411834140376,31.9596192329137));
#567=CARTESIAN_POINT('',(-4.6235856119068,30.5260545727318,31.7248239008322));
#568=CARTESIAN_POINT('',(-4.32339145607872,30.734253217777,31.2525527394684));
#569=CARTESIAN_POINT('',(-4.16838407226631,30.828228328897,31.0150765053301));
#570=CARTESIAN_POINT('',(-3.73129394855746,31.0589375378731,30.3590095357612));
#571=CARTESIAN_POINT('',(-3.44117937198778,31.174802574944,29.9383011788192));
#572=CARTESIAN_POINT('',(-2.84762630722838,31.3442303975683,29.0945856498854));
#573=CARTESIAN_POINT('',(-2.54420685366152,31.3978793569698,28.6715824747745));
#574=CARTESIAN_POINT('',(-2.23491225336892,31.4206127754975,28.2435645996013));
#575=CARTESIAN_POINT('',(-2.23101080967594,31.4208944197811,28.238166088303));
#576=CARTESIAN_POINT('',(-2.22710905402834,31.4211709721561,28.232767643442));
#577=B_SPLINE_CURVE_WITH_KNOTS('',3,(#559,#560,#561,#562,#563,#564,#565,#566,#567,#568,#569,
#570,#571,#572,#573,#574,#575,#576),.UNSPECIFIED.,.F.,.F.,(4,2,2,2,2,2,2,2,4),(0.,
0.449122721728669,0.898164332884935,1.79531890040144,2.69069063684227,3.58619944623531,
5.15404423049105,6.71971483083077,6.73971483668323),.UNSPECIFIED.);
#578=CARTESIAN_POINT('',(-5.66026089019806,29.4179244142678,33.5685341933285));
#579=VERTEX_POINT('',#578);
#580=EDGE_CURVE('E281',#579,#153,#577,.T.);
#581=ORIENTED_EDGE('',*,*,#580,.F.);
#582=CARTESIAN_POINT('',(-5.66012837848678,29.4181244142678,33.5682625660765));
#583=CARTESIAN_POINT('',(-5.70908256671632,29.3442366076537,33.6686200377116));
#584=CARTESIAN_POINT('',(-5.75980896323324,29.268644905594,33.7668270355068));
#585=CARTESIAN_POINT('',(-5.86479233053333,29.1143829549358,33.9588187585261));
#586=CARTESIAN_POINT('',(-5.91904894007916,29.0357130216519,34.0526039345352));
#587=CARTESIAN_POINT('',(-6.08695745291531,28.7957728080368,34.3269275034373));
#588=CARTESIAN_POINT('',(-6.20588041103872,28.6303706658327,34.5007057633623));
#589=CARTESIAN_POINT('',(-6.45596580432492,28.2932842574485,34.8277435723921));
#590=CARTESIAN_POINT('',(-6.58698706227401,28.1216838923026,34.9811988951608));
#591=CARTESIAN_POINT('',(-6.86173785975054,27.7732347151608,35.269740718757));
#592=CARTESIAN_POINT('',(-7.00547022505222,27.5963847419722,35.4048231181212));
#593=CARTESIAN_POINT('',(-7.30424916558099,27.2407290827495,35.656514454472));
#594=CARTESIAN_POINT('',(-7.45924876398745,27.0619338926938,35.7731943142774));
#595=CARTESIAN_POINT('',(-7.78020110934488,26.7039606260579,35.9895520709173));
#596=CARTESIAN_POINT('',(-7.94615324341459,26.524782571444,36.0892309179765));
#597=CARTESIAN_POINT('',(-8.28859577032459,26.1674933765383,36.2729487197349));
#598=CARTESIAN_POINT('',(-8.46511292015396,25.9893863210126,36.3569455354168));
#599=CARTESIAN_POINT('',(-8.82742645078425,25.6363270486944,36.5102500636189));
#600=CARTESIAN_POINT('',(-9.01322415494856,25.4613752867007,36.5795556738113));
#601=CARTESIAN_POINT('',(-9.49615408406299,25.0224713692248,36.7386892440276));
#602=CARTESIAN_POINT('',(-9.79913285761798,24.7615817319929,36.8193317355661));
#603=CARTESIAN_POINT('',(-10.4225898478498,24.2540302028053,36.9533589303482));
#604=CARTESIAN_POINT('',(-10.7430763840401,24.0073751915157,37.0067305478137));
#605=CARTESIAN_POINT('',(-11.3999547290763,23.5302607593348,37.0898207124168));
#606=CARTESIAN_POINT('',(-11.7363823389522,23.2998409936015,37.119483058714));
#607=CARTESIAN_POINT('',(-12.4223252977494,22.8576191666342,37.1571347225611));
#608=CARTESIAN_POINT('',(-12.7718388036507,22.645814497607,37.1651270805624));
#609=CARTESIAN_POINT('',(-13.4903205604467,22.2373452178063,37.1600152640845));
#610=CARTESIAN_POINT('',(-13.8595526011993,22.041150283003,37.1464135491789));
#611=CARTESIAN_POINT('',(-14.6074239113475,21.670635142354,37.0960743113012));
#612=CARTESIAN_POINT('',(-14.9860648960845,21.4963189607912,37.0593325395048));
#613=CARTESIAN_POINT('',(-15.7489092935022,21.1709092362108,36.9600374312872));
#614=CARTESIAN_POINT('',(-16.1330980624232,21.0197636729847,36.8975431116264));
#615=CARTESIAN_POINT('',(-16.9039237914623,20.7410327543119,36.7425972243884));
#616=CARTESIAN_POINT('',(-17.2905593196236,20.6134347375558,36.6501618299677));
#617=CARTESIAN_POINT('',(-17.9355827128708,20.4198317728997,36.4661445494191));
#618=CARTESIAN_POINT('',(-18.1947496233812,20.3472975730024,36.3840790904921));
#619=CARTESIAN_POINT('',(-18.7097312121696,20.2131016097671,36.2024848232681));
#620=CARTESIAN_POINT('',(-18.9655468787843,20.1514365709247,36.1029612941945));
#621=CARTESIAN_POINT('',(-19.4707327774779,20.0389492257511,35.8853173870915));
#622=CARTESIAN_POINT('',(-19.7201191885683,19.9880967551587,35.7672503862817));
#623=CARTESIAN_POINT('',(-20.210414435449,19.8966287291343,35.5111947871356));
#624=CARTESIAN_POINT('',(-20.4513248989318,19.8560111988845,35.3732100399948));
#625=CARTESIAN_POINT('',(-20.8665614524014,19.7927457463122,35.111407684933));
#626=CARTESIAN_POINT('',(-21.0432726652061,19.7681170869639,34.9918351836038));
#627=CARTESIAN_POINT('',(-21.3885166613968,19.7240729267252,34.7405916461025));
#628=CARTESIAN_POINT('',(-21.5570515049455,19.7046561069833,34.6089236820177));
#629=CARTESIAN_POINT('',(-21.885682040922,19.6704267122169,34.3326722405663));
#630=CARTESIAN_POINT('',(-22.0457122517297,19.6556464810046,34.1880067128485));
#631=CARTESIAN_POINT('',(-22.3548202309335,19.6302685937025,33.8868792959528));
#632=CARTESIAN_POINT('',(-22.5038905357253,19.6196737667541,33.7304095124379));
#633=CARTESIAN_POINT('',(-22.6467394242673,19.6108796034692,33.568307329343));
#634=B_SPLINE_CURVE_WITH_KNOTS('',3,(#582,#583,#584,#585,#586,#587,#588,#589,#590,#591,#592,
#593,#594,#595,#596,#597,#598,#599,#600,#601,#602,#603,#604,#605,#606,#607,#608,#609,#610,#611,
#612,#613,#614,#615,#616,#617,#618,#619,#620,#621,#622,#623,#624,#625,#626,#627,#628,#629,#630,
#631,#632,#633),.UNSPECIFIED.,.F.,.F.,(4,2,2,2,2,2,2,2,2,2,2,2,2,2,2,2,2,2,2,2,2,2,2,2,2,4),(0.,
0.401596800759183,0.803152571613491,1.6051786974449,2.39880796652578,3.19261411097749,
3.98328197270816,4.77390562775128,5.56662410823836,6.35945595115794,7.5812625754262,
8.80365492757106,10.0289363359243,11.2540458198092,12.50779463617,13.7617737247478,
15.0128949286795,16.2633414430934,17.1067530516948,17.9499100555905,18.7906830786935,
19.6312937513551,20.27512276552,20.9187887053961,21.566849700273,22.2153480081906),.UNSPECIFIED.);
#635=CARTESIAN_POINT('',(-22.6465394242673,19.610891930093,33.568534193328));
#636=VERTEX_POINT('',#635);
#637=EDGE_CURVE('E287',#579,#636,#634,.T.);
#638=ORIENTED_EDGE('',*,*,#637,.T.);
#639=CARTESIAN_POINT('',(-26.0979777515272,17.639318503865,28.232767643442));
#640=CARTESIAN_POINT('',(-26.0957873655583,17.6425592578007,28.2381661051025));
#641=CARTESIAN_POINT('',(-26.0935927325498,17.6457971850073,28.24356461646));
#642=CARTESIAN_POINT('',(-25.9715048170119,17.8254189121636,28.5433082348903));
#643=CARTESIAN_POINT('',(-25.839007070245,17.9933768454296,28.837789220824));
#644=CARTESIAN_POINT('',(-25.5505586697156,18.3097082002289,29.4258443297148));
#645=CARTESIAN_POINT('',(-25.3945993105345,18.4580743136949,29.7194180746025));
#646=CARTESIAN_POINT('',(-25.0606133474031,18.7326906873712,30.305118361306));
#647=CARTESIAN_POINT('',(-24.8825534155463,18.8589068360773,30.5972420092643));
#648=CARTESIAN_POINT('',(-24.5064415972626,19.0858432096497,31.1782260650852));
#649=CARTESIAN_POINT('',(-24.3084021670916,19.1865791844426,31.4670883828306));
#650=CARTESIAN_POINT('',(-23.8777210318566,19.3661170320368,32.0631220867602));
#651=CARTESIAN_POINT('',(-23.6435822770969,19.4425638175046,32.3699417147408));
#652=CARTESIAN_POINT('',(-23.2789979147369,19.5283534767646,32.8243186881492));
#653=CARTESIAN_POINT('',(-23.1553286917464,19.5521302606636,32.9747024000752));
#654=CARTESIAN_POINT('',(-22.903833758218,19.5894090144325,33.2733876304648));
#655=CARTESIAN_POINT('',(-22.7760057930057,19.6029053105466,33.4216879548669));
#656=CARTESIAN_POINT('',(-22.6463394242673,19.610904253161,33.5687610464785));
#657=B_SPLINE_CURVE_WITH_KNOTS('',3,(#639,#640,#641,#642,#643,#644,#645,#646,#647,#648,#649,
#650,#651,#652,#653,#654,#655,#656),.UNSPECIFIED.,.F.,.F.,(4,2,2,2,2,2,2,2,4),(0.,
0.0200000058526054,1.11045859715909,2.20132280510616,3.29385250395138,4.3857052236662,
5.56362960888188,6.15179569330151,6.74028614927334),.UNSPECIFIED.);
#658=EDGE_CURVE('E294',#130,#636,#657,.T.);
#659=ORIENTED_EDGE('',*,*,#658,.F.);
#660=ORIENTED_EDGE('',*,*,#131,.T.);
#661=CARTESIAN_POINT('',(-28.3067007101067,9.80683248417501,33.568787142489));
#662=CARTESIAN_POINT('',(-28.35089128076,9.89556849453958,33.456561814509));
#663=CARTESIAN_POINT('',(-28.3917729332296,9.98498886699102,33.3436125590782));
#664=CARTESIAN_POINT('',(-28.4670914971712,10.1648549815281,33.1164224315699));
#665=CARTESIAN_POINT('',(-28.5015295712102,10.2553005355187,33.0021817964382));
#666=CARTESIAN_POINT('',(-28.5953953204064,10.5275208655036,32.6579333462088));
#667=CARTESIAN_POINT('',(-28.6454651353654,10.7103641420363,32.4261663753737));
#668=CARTESIAN_POINT('',(-28.7218108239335,11.0760554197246,31.9595965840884));
#669=CARTESIAN_POINT('',(-28.7481337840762,11.2589026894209,31.7248007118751));
#670=CARTESIAN_POINT('',(-28.7783405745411,11.6229783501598,31.2525284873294));
#671=CARTESIAN_POINT('',(-28.7822209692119,11.8042064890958,31.0150517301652));
#672=CARTESIAN_POINT('',(-28.7634739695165,12.2980890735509,30.3589883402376));
#673=CARTESIAN_POINT('',(-28.7187582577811,12.6072648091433,29.9382841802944));
#674=CARTESIAN_POINT('',(-28.5687108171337,13.206004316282,29.0945771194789));
#675=CARTESIAN_POINT('',(-28.4634632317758,13.4955946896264,28.6715782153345));
#676=CARTESIAN_POINT('',(-28.3285049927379,13.7748156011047,28.2435645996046));
#677=CARTESIAN_POINT('',(-28.3267981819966,13.7783351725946,28.2381660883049));
#678=CARTESIAN_POINT('',(-28.3250868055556,13.7818524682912,28.232767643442));
#679=B_SPLINE_CURVE_WITH_KNOTS('',3,(#661,#662,#663,#664,#665,#666,#667,#668,#669,#670,#671,
#672,#673,#674,#675,#676,#677,#678),.UNSPECIFIED.,.F.,.F.,(4,2,2,2,2,2,2,2,4),(0.,
0.449123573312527,0.898166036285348,1.79532231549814,2.69069573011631,3.58620621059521,
5.15403517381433,6.71968999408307,6.73968999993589),.UNSPECIFIED.);
#680=CARTESIAN_POINT('',(-28.3068003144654,9.80703248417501,33.5685341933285));
#681=VERTEX_POINT('',#680);
#682=EDGE_CURVE('E317',#681,#126,#679,.T.);
#683=ORIENTED_EDGE('',*,*,#682,.F.);
#684=CARTESIAN_POINT('',(-28.306899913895,9.807232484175,33.5682812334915));
#685=CARTESIAN_POINT('',(-28.2673881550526,9.72789258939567,33.6686385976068));
#686=CARTESIAN_POINT('',(-28.2272868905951,9.64616596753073,33.7668454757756));
#687=CARTESIAN_POINT('',(-28.1461835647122,9.4781158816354,33.9588369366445));
#688=CARTESIAN_POINT('',(-28.1051815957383,9.39179288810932,34.0526219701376));
#689=CARTESIAN_POINT('',(-27.9813412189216,9.12640847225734,34.3269450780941));
#690=CARTESIAN_POINT('',(-27.8975600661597,8.94071625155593,34.5007229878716));
#691=CARTESIAN_POINT('',(-27.7306770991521,8.55559108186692,34.8277600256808));
#692=CARTESIAN_POINT('',(-27.6475773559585,8.35632234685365,34.9812149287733));
#693=CARTESIAN_POINT('',(-27.4831867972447,7.94415498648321,35.2697558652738));
#694=CARTESIAN_POINT('',(-27.4018963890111,7.73125333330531,35.4048377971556));
#695=CARTESIAN_POINT('',(-27.2432790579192,7.29467382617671,35.656528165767));
#696=CARTESIAN_POINT('',(-27.1659377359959,7.07104190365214,35.7732075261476));
#697=CARTESIAN_POINT('',(-27.0164001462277,6.61410095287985,35.9895642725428));
#698=CARTESIAN_POINT('',(-26.9442035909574,6.38079246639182,36.0892426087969));
#699=CARTESIAN_POINT('',(-26.8060036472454,5.9055825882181,36.2729593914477));
#700=CARTESIAN_POINT('',(-26.7400171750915,5.66366006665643,36.3569556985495));
#701=CARTESIAN_POINT('',(-26.6154160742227,5.17335643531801,36.510259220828));
#702=CARTESIAN_POINT('',(-26.5568025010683,4.92497440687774,36.5795643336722));
#703=CARTESIAN_POINT('',(-26.4181661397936,4.28729101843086,36.738696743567));
#704=CARTESIAN_POINT('',(-26.3437188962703,3.89445767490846,36.8193385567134));
#705=CARTESIAN_POINT('',(-26.2158958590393,3.10074997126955,36.9533643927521));
#706=CARTESIAN_POINT('',(-26.1625301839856,2.69987184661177,37.006735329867));
#707=CARTESIAN_POINT('',(-26.0777773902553,1.8924390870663,37.0898241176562));
#708=CARTESIAN_POINT('',(-26.0464425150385,1.48587327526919,37.1194857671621));
#709=CARTESIAN_POINT('',(-26.0064401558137,0.670716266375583,37.1571359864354));
#710=CARTESIAN_POINT('',(-25.9977694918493,0.262125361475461,37.1651275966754));
#711=CARTESIAN_POINT('',(-26.0032673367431,-0.564334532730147,37.1600141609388));
#712=CARTESIAN_POINT('',(-26.01797448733,-0.982197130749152,37.146411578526));
#713=CARTESIAN_POINT('',(-26.0710365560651,-1.81513174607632,37.0960704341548));
#714=CARTESIAN_POINT('',(-26.1093958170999,-2.23020323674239,37.0593276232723));
#715=CARTESIAN_POINT('',(-26.2090070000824,-3.05355191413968,36.9600301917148));
#716=CARTESIAN_POINT('',(-26.2702065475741,-3.46184242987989,36.8975345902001));
#717=CARTESIAN_POINT('',(-26.4142334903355,-4.26876333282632,36.7425858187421));
#718=CARTESIAN_POINT('',(-26.4970492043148,-4.66739881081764,36.650148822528));
#719=CARTESIAN_POINT('',(-26.65189721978,-5.32280567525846,36.4661289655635));
#720=CARTESIAN_POINT('',(-26.7186645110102,-5.58351647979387,36.3840627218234));
#721=CARTESIAN_POINT('',(-26.8599386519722,-6.09659869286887,36.2024669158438));
#722=CARTESIAN_POINT('',(-26.9344431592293,-6.34897259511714,36.1029426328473));
#723=CARTESIAN_POINT('',(-27.0896194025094,-6.84271708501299,35.8852972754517));
#724=CARTESIAN_POINT('',(-27.1702731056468,-7.08411676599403,35.7672295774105));
#725=CARTESIAN_POINT('',(-27.336207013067,-7.55445583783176,35.5111726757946));
#726=CARTESIAN_POINT('',(-27.4214863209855,-7.78339762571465,35.3731873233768));
#727=CARTESIAN_POINT('',(-27.5743147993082,-8.17463300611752,35.1113840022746));
#728=CARTESIAN_POINT('',(-27.6413411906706,-8.33998254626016,34.9918111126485));
#729=CARTESIAN_POINT('',(-27.7758194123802,-8.66099232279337,34.7405668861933));
#730=CARTESIAN_POINT('',(-27.8432711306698,-8.81665500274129,34.6088986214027));
#731=CARTESIAN_POINT('',(-27.9779423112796,-9.11836971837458,34.332646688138));
#732=CARTESIAN_POINT('',(-28.0451570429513,-9.26434887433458,34.187980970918));
#733=CARTESIAN_POINT('',(-28.177732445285,-9.54473083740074,33.8868532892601));
#734=CARTESIAN_POINT('',(-28.2430918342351,-9.67912576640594,33.730383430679));
#735=CARTESIAN_POINT('',(-28.306899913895,-9.807232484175,33.5682812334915));
#736=B_SPLINE_CURVE_WITH_KNOTS('',3,(#684,#685,#686,#687,#688,#689,#690,#691,#692,#693,#694,
#695,#696,#697,#698,#699,#700,#701,#702,#703,#704,#705,#706,#707,#708,#709,#710,#711,#712,#713,
#714,#715,#716,#717,#718,#719,#720,#721,#722,#723,#724,#725,#726,#727,#728,#729,#730,#731,#732,
#733,#734,#735),.UNSPECIFIED.,.F.,.F.,(4,2,2,2,2,2,2,2,2,2,2,2,2,2,2,2,2,2,2,2,2,2,2,2,2,4),(0.,
0.401597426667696,0.803153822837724,1.6051811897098,2.39881165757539,3.19261900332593,
3.98328802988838,4.77391284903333,5.56663251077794,6.35946553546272,7.58127502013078,
8.80367023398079,10.0289545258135,11.2540668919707,12.5078182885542,13.7617999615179,
15.0129236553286,16.2633726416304,17.1067811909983,17.9499351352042,18.7907051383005,
19.6313127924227,20.2751395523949,20.9188032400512,21.5668619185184,22.2153579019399),.UNSPECIFIED.);
#737=CARTESIAN_POINT('',(-28.3068003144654,-9.807032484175,33.5685341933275));
#738=VERTEX_POINT('',#737);
#739=EDGE_CURVE('E323',#681,#738,#736,.T.);
#740=ORIENTED_EDGE('',*,*,#739,.T.);
#741=CARTESIAN_POINT('',(-28.3250868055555,-13.7818524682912,28.232767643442));
#742=CARTESIAN_POINT('',(-28.3267981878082,-13.7783351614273,28.2381661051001));
#743=CARTESIAN_POINT('',(-28.3285049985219,-13.7748155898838,28.2435646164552));
#744=CARTESIAN_POINT('',(-28.423018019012,-13.5792734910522,28.5433082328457));
#745=CARTESIAN_POINT('',(-28.5022249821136,-13.3805481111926,28.8377892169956));
#746=CARTESIAN_POINT('',(-28.6319517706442,-12.9725787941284,29.4258443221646));
#747=CARTESIAN_POINT('',(-28.6824609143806,-12.7633309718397,29.7194180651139));
#748=CARTESIAN_POINT('',(-28.7532926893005,-12.3367824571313,30.3051183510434));
#749=CARTESIAN_POINT('',(-28.7735691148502,-12.119469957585,30.5972420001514));
#750=CARTESIAN_POINT('',(-28.7820458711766,-11.6802793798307,31.1782260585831));
#751=CARTESIAN_POINT('',(-28.7702660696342,-11.4584042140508,31.4670883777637));
#752=CARTESIAN_POINT('',(-28.7104093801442,-10.9956509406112,32.0631266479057));
#753=CARTESIAN_POINT('',(-28.659543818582,-10.7546538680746,32.3699507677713));
#754=CARTESIAN_POINT('',(-28.5515451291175,-10.3960144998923,32.824334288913));
#755=CARTESIAN_POINT('',(-28.5103008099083,-10.2770236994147,32.9747201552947));
#756=CARTESIAN_POINT('',(-28.4168353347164,-10.0405799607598,33.2734096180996));
#757=CARTESIAN_POINT('',(-28.364608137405,-9.92312790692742,33.4217120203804));
#758=CARTESIAN_POINT('',(-28.3067007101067,-9.8068324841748,33.568787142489));
#759=B_SPLINE_CURVE_WITH_KNOTS('',3,(#741,#742,#743,#744,#745,#746,#747,#748,#749,#750,#751,
#752,#753,#754,#755,#756,#757,#758),.UNSPECIFIED.,.F.,.F.,(4,2,2,2,2,2,2,2,4),(0.,
0.020000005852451,1.11045859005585,2.20132279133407,3.29385249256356,4.38570522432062,
5.5636469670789,6.15182175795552,6.74032093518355),.UNSPECIFIED.);
#760=EDGE_CURVE('E330',#103,#738,#759,.T.);
#761=ORIENTED_EDGE('',*,*,#760,.F.);
#762=ORIENTED_EDGE('',*,*,#104,.T.);
#763=CARTESIAN_POINT('',(-22.6463394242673,-19.6109042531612,33.5687610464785));
#764=CARTESIAN_POINT('',(-22.7452824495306,-19.604805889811,33.456535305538));
#765=CARTESIAN_POINT('',(-22.8431636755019,-19.5954997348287,33.3435856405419));
#766=CARTESIAN_POINT('',(-23.0365917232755,-19.5707934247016,33.116394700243));
#767=CARTESIAN_POINT('',(-23.132138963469,-19.5553943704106,33.0021536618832));
#768=CARTESIAN_POINT('',(-23.414821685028,-19.5005727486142,32.657904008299));
#769=CARTESIAN_POINT('',(-23.5982035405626,-19.4525117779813,32.4261362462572));
#770=CARTESIAN_POINT('',(-23.9530742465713,-19.3357813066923,31.9595649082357));
#771=CARTESIAN_POINT('',(-24.1245860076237,-19.2671529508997,31.7247682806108));
#772=CARTESIAN_POINT('',(-24.4549878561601,-19.1112728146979,31.2524945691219));
#773=CARTESIAN_POINT('',(-24.613876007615,-19.0240181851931,31.0150170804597));
#774=CARTESIAN_POINT('',(-25.0322121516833,-18.7608413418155,30.3589586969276));
#775=CARTESIAN_POINT('',(-25.2776039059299,-18.5675303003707,29.9382604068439));
#776=CARTESIAN_POINT('',(-25.7210962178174,-18.1382205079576,29.0945651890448));
#777=CARTESIAN_POINT('',(-25.9192618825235,-17.9022813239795,28.6715722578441));
#778=CARTESIAN_POINT('',(-26.0935927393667,-17.6457971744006,28.243564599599));
#779=CARTESIAN_POINT('',(-26.0957873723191,-17.6425592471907,28.2381660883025));
#780=CARTESIAN_POINT('',(-26.0979777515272,-17.639318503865,28.232767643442));
#781=B_SPLINE_CURVE_WITH_KNOTS('',3,(#763,#764,#765,#766,#767,#768,#769,#770,#771,#772,#773,
#774,#775,#776,#777,#778,#779,#780),.UNSPECIFIED.,.F.,.F.,(4,2,2,2,2,2,2,2,4),(0.,
0.449124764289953,0.898168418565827,1.79532709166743,2.69070285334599,3.58621567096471,
5.15402250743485,6.71965525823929,6.73965526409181),.UNSPECIFIED.);
#782=CARTESIAN_POINT('',(-22.6465394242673,-19.610891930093,33.5685341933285));
#783=VERTEX_POINT('',#782);
#784=EDGE_CURVE('E336',#783,#99,#781,.T.);
#785=ORIENTED_EDGE('',*,*,#784,.F.);
#786=CARTESIAN_POINT('',(-22.6467394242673,-19.6108796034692,33.568307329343));
#787=CARTESIAN_POINT('',(-22.5582725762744,-19.6163314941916,33.6686645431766));
#788=CARTESIAN_POINT('',(-22.4674440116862,-19.622466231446,33.7668712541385));
#789=CARTESIAN_POINT('',(-22.2813555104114,-19.6362540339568,33.9588623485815));
#790=CARTESIAN_POINT('',(-22.1860960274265,-19.6439069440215,34.0526471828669));
#791=CARTESIAN_POINT('',(-21.8943444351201,-19.6693507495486,34.3269696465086));
#792=CARTESIAN_POINT('',(-21.6916385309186,-19.689640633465,34.5007470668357));
#793=CARTESIAN_POINT('',(-21.2746666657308,-19.737679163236,34.8277830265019));
#794=CARTESIAN_POINT('',(-21.0605439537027,-19.7653474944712,34.9812373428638));
#795=CARTESIAN_POINT('',(-20.6213992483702,-19.8290657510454,35.2697770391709));
#796=CARTESIAN_POINT('',(-20.3963748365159,-19.8651175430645,35.4048583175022));
#797=CARTESIAN_POINT('',(-19.9389754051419,-19.9460417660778,35.6565473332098));
#798=CARTESIAN_POINT('',(-19.7066329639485,-19.990878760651,35.7732259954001));
#799=CARTESIAN_POINT('',(-19.2361400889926,-20.089847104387,35.9895813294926));
#800=CARTESIAN_POINT('',(-18.9979899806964,-20.1439779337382,36.0892589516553));
#801=CARTESIAN_POINT('',(-18.5173447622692,-20.2618995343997,36.2729743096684));
#802=CARTESIAN_POINT('',(-18.2748398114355,-20.3257155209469,36.356969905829));
#803=CARTESIAN_POINT('',(-17.7879226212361,-20.4629610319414,36.5102720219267));
#804=CARTESIAN_POINT('',(-17.5435101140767,-20.536391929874,36.5795764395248));
#805=CARTESIAN_POINT('',(-16.9219401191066,-20.7351730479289,36.7387072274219));
#806=CARTESIAN_POINT('',(-16.5445116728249,-20.8671178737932,36.8193480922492));
#807=CARTESIAN_POINT('',(-15.7932269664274,-21.1532765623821,36.9533720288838));
#808=CARTESIAN_POINT('',(-15.4193725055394,-21.3075010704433,37.0067420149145));
#809=CARTESIAN_POINT('',(-14.677737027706,-21.6378224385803,37.0898288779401));
#810=CARTESIAN_POINT('',(-14.3099724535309,-21.813970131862,37.1194895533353));
#811=CARTESIAN_POINT('',(-13.5840231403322,-22.1869088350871,37.1571377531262));
#812=CARTESIAN_POINT('',(-13.2258370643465,-22.3836969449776,37.1651283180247));
#813=CARTESIAN_POINT('',(-12.5128497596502,-22.8016915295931,37.1600126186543));
#814=CARTESIAN_POINT('',(-12.1583233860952,-23.0233612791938,37.146408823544));
#815=CARTESIAN_POINT('',(-11.4635114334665,-23.4857850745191,37.0960650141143));
#816=CARTESIAN_POINT('',(-11.1232284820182,-23.7265426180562,37.0593207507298));
#817=CARTESIAN_POINT('',(-10.4599932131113,-24.2244861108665,36.9600200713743));
#818=CARTESIAN_POINT('',(-10.1370031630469,-24.4816333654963,36.8975226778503));
#819=CARTESIAN_POINT('',(-9.510203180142,-25.0098279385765,36.7425698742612));
#820=CARTESIAN_POINT('',(-9.20638299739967,-25.2808676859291,36.6501306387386));
#821=CARTESIAN_POINT('',(-8.71621052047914,-25.7426742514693,36.466107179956));
#822=CARTESIAN_POINT('',(-8.52381391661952,-25.9308511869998,36.384039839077));
#823=CARTESIAN_POINT('',(-8.15011259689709,-26.3097378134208,36.2024418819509));
#824=CARTESIAN_POINT('',(-7.96880455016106,-26.5004467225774,36.1029165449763));
#825=CARTESIAN_POINT('',(-7.61880117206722,-26.8817036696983,35.8852691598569));
#826=CARTESIAN_POINT('',(-7.45007162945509,-27.0722506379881,35.767200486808));
#827=CARTESIAN_POINT('',(-7.1257166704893,-27.4511209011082,35.5111417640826));
#828=CARTESIAN_POINT('',(-6.97008873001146,-27.6394446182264,35.3731555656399));
#829=CARTESIAN_POINT('',(-6.70768734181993,-27.9674120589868,35.1113519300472));
#830=CARTESIAN_POINT('',(-6.59800591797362,-28.1081310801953,34.9917796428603));
#831=CARTESIAN_POINT('',(-6.38724675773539,-28.3850929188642,34.7405369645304));
#832=CARTESIAN_POINT('',(-6.28616684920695,-28.5213368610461,34.6088696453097));
#833=CARTESIAN_POINT('',(-6.09221377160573,-28.7888183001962,34.3326200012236));
#834=CARTESIAN_POINT('',(-5.99940134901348,-28.9200152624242,34.1879556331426));
#835=CARTESIAN_POINT('',(-5.82287463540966,-29.175015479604,33.8868310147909));
#836=CARTESIAN_POINT('',(-5.73916652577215,-29.2988136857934,33.7303628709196));
#837=CARTESIAN_POINT('',(-5.66012837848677,-29.418124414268,33.5682625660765));
#838=B_SPLINE_CURVE_WITH_KNOTS('',3,(#786,#787,#788,#789,#790,#791,#792,#793,#794,#795,#796,
#797,#798,#799,#800,#801,#802,#803,#804,#805,#806,#807,#808,#809,#810,#811,#812,#813,#814,#815,
#816,#817,#818,#819,#820,#821,#822,#823,#824,#825,#826,#827,#828,#829,#830,#831,#832,#833,#834,
#835,#836,#837),.UNSPECIFIED.,.F.,.F.,(4,2,2,2,2,2,2,2,2,2,2,2,2,2,2,2,2,2,2,2,2,2,2,2,2,4),(0.,
0.40159830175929,0.803155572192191,1.60518467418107,2.39881681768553,3.19262584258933,
3.98329649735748,4.77392294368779,5.56664425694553,6.35947893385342,7.58129241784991,
8.80369163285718,10.0289799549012,11.2540963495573,12.507851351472,13.7618366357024,
15.0129638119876,16.2634162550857,17.1068205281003,17.949970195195,18.7907359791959,
19.6313394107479,20.2751571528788,20.9188118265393,21.5668612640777,22.2153479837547),.UNSPECIFIED.);
#839=CARTESIAN_POINT('',(-5.66026089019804,-29.417924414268,33.5685341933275));
#840=VERTEX_POINT('',#839);
#841=EDGE_CURVE('E360',#783,#840,#838,.T.);
#842=ORIENTED_EDGE('',*,*,#841,.T.);
#843=CARTESIAN_POINT('',(-2.22710905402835,-31.421170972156,28.232767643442));
#844=CARTESIAN_POINT('',(-2.23101082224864,-31.4208944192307,28.2381661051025));
#845=CARTESIAN_POINT('',(-2.23491226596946,-31.4206127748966,28.2435646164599));
#846=CARTESIAN_POINT('',(-2.45151320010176,-31.4046924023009,28.5433082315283));
#847=CARTESIAN_POINT('',(-2.66321790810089,-31.3739249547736,28.8377892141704));
#848=CARTESIAN_POINT('',(-3.08139309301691,-31.2822869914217,29.4258443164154));
#849=CARTESIAN_POINT('',(-3.28786159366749,-31.2214052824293,29.719418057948));
#850=CARTESIAN_POINT('',(-3.69267933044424,-31.0694731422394,30.3051183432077));
#851=CARTESIAN_POINT('',(-3.89101568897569,-30.9783767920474,30.5972419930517));
#852=CARTESIAN_POINT('',(-4.2756042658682,-30.7661225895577,31.1782260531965));
#853=CARTESIAN_POINT('',(-4.46186389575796,-30.6449833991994,31.4670883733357));
#854=CARTESIAN_POINT('',(-4.83269367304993,-30.3617677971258,32.0631299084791));
#855=CARTESIAN_POINT('',(-5.01597231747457,-30.1972164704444,32.3699572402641));
#856=CARTESIAN_POINT('',(-5.27256610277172,-29.9243637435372,32.8243454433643));
#857=CARTESIAN_POINT('',(-5.35499370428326,-29.8291484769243,32.9747328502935));
#858=CARTESIAN_POINT('',(-5.51302848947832,-29.6299804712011,33.2734253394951));
#859=CARTESIAN_POINT('',(-5.58863188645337,-29.5260229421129,33.4217292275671));
#860=CARTESIAN_POINT('',(-5.66039339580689,-29.417724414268,33.5688058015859));
#861=B_SPLINE_CURVE_WITH_KNOTS('',3,(#843,#844,#845,#846,#847,#848,#849,#850,#851,#852,#853,
#854,#855,#856,#857,#858,#859,#860),.UNSPECIFIED.,.F.,.F.,(4,2,2,2,2,2,2,2,4),(0.,
0.0200000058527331,1.11045858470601,2.20132278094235,3.29385248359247,4.38570522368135,
5.56365937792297,6.15184039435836,6.74034580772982),.UNSPECIFIED.);
#862=EDGE_CURVE('E367',#76,#840,#861,.T.);
#863=ORIENTED_EDGE('',*,*,#862,.F.);
#864=ORIENTED_EDGE('',*,*,#77,.T.);
#865=CARTESIAN_POINT('',(5.6603933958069,-29.417724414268,33.5688058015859));
#866=CARTESIAN_POINT('',(5.60564139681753,-29.5003626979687,33.4565807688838));
#867=CARTESIAN_POINT('',(5.54864226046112,-29.580477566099,33.3436318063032));
#868=CARTESIAN_POINT('',(5.43053361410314,-29.7356386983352,33.1164422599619));
#869=CARTESIAN_POINT('',(5.36942484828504,-29.8106858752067,33.0022019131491));
#870=CARTESIAN_POINT('',(5.18060902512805,-30.02808665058,32.6579543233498));
#871=CARTESIAN_POINT('',(5.04729767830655,-30.1628703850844,32.4261879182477));
#872=CARTESIAN_POINT('',(4.76877388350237,-30.4118341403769,31.9596192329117));
#873=CARTESIAN_POINT('',(4.62358561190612,-30.5260545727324,31.7248239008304));
#874=CARTESIAN_POINT('',(4.32339145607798,-30.7342532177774,31.2525527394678));
#875=CARTESIAN_POINT('',(4.16838407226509,-30.8282283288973,31.0150765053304));
#876=CARTESIAN_POINT('',(3.7312939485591,-31.058937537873,30.3590095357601));
#877=CARTESIAN_POINT('',(3.44117937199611,-31.1748025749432,29.9383011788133));
#878=CARTESIAN_POINT('',(2.84762630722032,-31.3442303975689,29.0945856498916));
#879=CARTESIAN_POINT('',(2.54420685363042,-31.3978793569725,28.6715824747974));
#880=CARTESIAN_POINT('',(2.23491225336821,-31.4206127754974,28.2435645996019));
#881=CARTESIAN_POINT('',(2.23101080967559,-31.420894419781,28.2381660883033));
#882=CARTESIAN_POINT('',(2.22710905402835,-31.421170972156,28.232767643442));
#883=B_SPLINE_CURVE_WITH_KNOTS('',3,(#865,#866,#867,#868,#869,#870,#871,#872,#873,#874,#875,
#876,#877,#878,#879,#880,#881,#882),.UNSPECIFIED.,.F.,.F.,(4,2,2,2,2,2,2,2,4),(0.,
0.449122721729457,0.898164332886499,1.79531890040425,2.69069063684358,3.58619944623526,
5.15404423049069,6.71971483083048,6.73971483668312),.UNSPECIFIED.);
#884=CARTESIAN_POINT('',(5.66026089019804,-29.417924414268,33.5685341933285));
#885=VERTEX_POINT('',#884);
#886=EDGE_CURVE('E373',#885,#72,#883,.T.);
#887=ORIENTED_EDGE('',*,*,#886,.F.);
#888=CARTESIAN_POINT('',(5.66012837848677,-29.418124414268,33.5682625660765));
#889=CARTESIAN_POINT('',(5.70908256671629,-29.3442366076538,33.6686200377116));
#890=CARTESIAN_POINT('',(5.7598089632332,-29.268644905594,33.7668270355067));
#891=CARTESIAN_POINT('',(5.86479233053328,-29.1143829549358,33.958818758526));
#892=CARTESIAN_POINT('',(5.91904894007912,-29.035713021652,34.0526039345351));
#893=CARTESIAN_POINT('',(6.08695745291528,-28.7957728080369,34.3269275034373));
#894=CARTESIAN_POINT('',(6.20588041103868,-28.6303706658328,34.5007057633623));
#895=CARTESIAN_POINT('',(6.45596580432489,-28.2932842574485,34.8277435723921));
#896=CARTESIAN_POINT('',(6.58698706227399,-28.1216838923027,34.9811988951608));
#897=CARTESIAN_POINT('',(6.86173785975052,-27.7732347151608,35.269740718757));
#898=CARTESIAN_POINT('',(7.0054702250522,-27.5963847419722,35.4048231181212));
#899=CARTESIAN_POINT('',(7.30424916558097,-27.2407290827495,35.656514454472));
#900=CARTESIAN_POINT('',(7.45924876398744,-27.0619338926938,35.7731943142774));
#901=CARTESIAN_POINT('',(7.78020110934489,-26.7039606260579,35.9895520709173));
#902=CARTESIAN_POINT('',(7.9461532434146,-26.524782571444,36.0892309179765));
#903=CARTESIAN_POINT('',(8.28859577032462,-26.1674933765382,36.2729487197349));
#904=CARTESIAN_POINT('',(8.465112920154,-25.9893863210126,36.3569455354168));
#905=CARTESIAN_POINT('',(8.82742645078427,-25.6363270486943,36.5102500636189));
#906=CARTESIAN_POINT('',(9.01322415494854,-25.4613752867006,36.5795556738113));
#907=CARTESIAN_POINT('',(9.49615408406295,-25.0224713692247,36.7386892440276));
#908=CARTESIAN_POINT('',(9.799132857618,-24.7615817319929,36.8193317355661));
#909=CARTESIAN_POINT('',(10.4225898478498,-24.2540302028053,36.9533589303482));
#910=CARTESIAN_POINT('',(10.7430763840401,-24.0073751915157,37.0067305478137));
#911=CARTESIAN_POINT('',(11.3999547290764,-23.5302607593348,37.0898207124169));
#912=CARTESIAN_POINT('',(11.7363823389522,-23.2998409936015,37.119483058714));
#913=CARTESIAN_POINT('',(12.4223252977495,-22.8576191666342,37.1571347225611));
#914=CARTESIAN_POINT('',(12.7718388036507,-22.645814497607,37.1651270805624));
#915=CARTESIAN_POINT('',(13.4903205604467,-22.2373452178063,37.1600152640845));
#916=CARTESIAN_POINT('',(13.8595526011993,-22.041150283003,37.1464135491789));
#917=CARTESIAN_POINT('',(14.6074239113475,-21.670635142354,37.0960743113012));
#918=CARTESIAN_POINT('',(14.9860648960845,-21.4963189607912,37.0593325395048));
#919=CARTESIAN_POINT('',(15.7489092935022,-21.1709092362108,36.9600374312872));
#920=CARTESIAN_POINT('',(16.1330980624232,-21.0197636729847,36.8975431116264));
#921=CARTESIAN_POINT('',(16.9039237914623,-20.7410327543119,36.7425972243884));
#922=CARTESIAN_POINT('',(17.2905593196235,-20.6134347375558,36.6501618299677));
#923=CARTESIAN_POINT('',(17.9355827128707,-20.4198317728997,36.4661445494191));
#924=CARTESIAN_POINT('',(18.1947496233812,-20.3472975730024,36.3840790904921));
#925=CARTESIAN_POINT('',(18.7097312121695,-20.2131016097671,36.2024848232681));
#926=CARTESIAN_POINT('',(18.9655468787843,-20.1514365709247,36.1029612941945));
#927=CARTESIAN_POINT('',(19.4707327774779,-20.0389492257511,35.8853173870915));
#928=CARTESIAN_POINT('',(19.7201191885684,-19.9880967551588,35.7672503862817));
#929=CARTESIAN_POINT('',(20.210414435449,-19.8966287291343,35.5111947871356));
#930=CARTESIAN_POINT('',(20.4513248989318,-19.8560111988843,35.3732100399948));
#931=CARTESIAN_POINT('',(20.8665614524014,-19.792745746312,35.111407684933));
#932=CARTESIAN_POINT('',(21.0432726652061,-19.7681170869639,34.9918351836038));
#933=CARTESIAN_POINT('',(21.3885166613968,-19.7240729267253,34.7405916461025));
#934=CARTESIAN_POINT('',(21.5570515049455,-19.7046561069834,34.6089236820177));
#935=CARTESIAN_POINT('',(21.885682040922,-19.6704267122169,34.3326722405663));
#936=CARTESIAN_POINT('',(22.0457122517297,-19.6556464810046,34.1880067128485));
#937=CARTESIAN_POINT('',(22.3548202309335,-19.6302685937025,33.8868792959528));
#938=CARTESIAN_POINT('',(22.5038905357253,-19.6196737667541,33.7304095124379));
#939=CARTESIAN_POINT('',(22.6467394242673,-19.6108796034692,33.568307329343));
#940=B_SPLINE_CURVE_WITH_KNOTS('',3,(#888,#889,#890,#891,#892,#893,#894,#895,#896,#897,#898,
#899,#900,#901,#902,#903,#904,#905,#906,#907,#908,#909,#910,#911,#912,#913,#914,#915,#916,#917,
#918,#919,#920,#921,#922,#923,#924,#925,#926,#927,#928,#929,#930,#931,#932,#933,#934,#935,#936,
#937,#938,#939),.UNSPECIFIED.,.F.,.F.,(4,2,2,2,2,2,2,2,2,2,2,2,2,2,2,2,2,2,2,2,2,2,2,2,2,4),(0.,
0.401596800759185,0.803152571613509,1.60517869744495,2.39880796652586,3.1926141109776,
3.98328197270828,4.77390562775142,5.56662410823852,6.35945595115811,7.58126257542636,
8.80365492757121,10.0289363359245,11.2540458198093,12.5077946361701,13.7617737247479,
15.0128949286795,16.2633414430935,17.1067530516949,17.9499100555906,18.7906830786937,
19.6312937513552,20.2751227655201,20.9187887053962,21.5668497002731,22.2153480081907),.UNSPECIFIED.);
#941=EDGE_CURVE('E204',#885,#351,#940,.T.);
#942=ORIENTED_EDGE('',*,*,#941,.T.);
#943=EDGE_LOOP('',(#353,#354,#377,#434,#455,#456,#479,#536,#557,#558,#581,#638,#659,#660,#683,
#740,#761,#762,#785,#842,#863,#864,#887,#942));
#944=FACE_BOUND('',#943,.T.);
#945=ORIENTED_EDGE('',*,*,#310,.F.);
#946=EDGE_LOOP('',(#945));
#947=FACE_BOUND('',#946,.T.);
#948=ADVANCED_FACE('F194',(#944,#947),#330,.T.);
#949=CARTESIAN_POINT('',(0.,29.,21.));
#950=DIRECTION('',(0.,0.,1.));
#951=DIRECTION('',(-1.,0.,0.));
#952=AXIS2_PLACEMENT_3D('',#949,#950,#951);
#953=PLANE('',#952);
#954=ORIENTED_EDGE('',*,*,#33,.F.);
#955=CARTESIAN_POINT('',(22.3696952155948,-15.1194158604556,21.));
#956=DIRECTION('',(0.,0.,1.));
#957=DIRECTION('',(-1.,0.,0.));
#958=AXIS2_PLACEMENT_3D('',#955,#956,#957);
#959=CIRCLE('',#958,4.5);
#960=CARTESIAN_POINT('',(22.6465394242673,-19.610891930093,21.));
#961=VERTEX_POINT('',#960);
#962=EDGE_CURVE('E9',#30,#961,#959,.F.);
#963=ORIENTED_EDGE('',*,*,#962,.T.);
#964=CARTESIAN_POINT('',(24.,-41.569219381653,21.));
#965=DIRECTION('',(0.,0.,1.));
#966=DIRECTION('',(-1.,0.,0.));
#967=AXIS2_PLACEMENT_3D('',#964,#965,#966);
#968=CIRCLE('',#967,22.);
#969=CARTESIAN_POINT('',(5.66026089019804,-29.417924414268,21.));
#970=VERTEX_POINT('',#969);
#971=EDGE_CURVE('E22',#970,#961,#968,.F.);
#972=ORIENTED_EDGE('',*,*,#971,.F.);
#973=CARTESIAN_POINT('',(1.90895061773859,-26.932432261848,21.));
#974=DIRECTION('',(0.,0.,1.));
#975=DIRECTION('',(-1.,0.,0.));
#976=AXIS2_PLACEMENT_3D('',#973,#974,#975);
#977=CIRCLE('',#976,4.5);
#978=EDGE_CURVE('E507',#970,#64,#977,.F.);
#979=ORIENTED_EDGE('',*,*,#978,.T.);
#980=ORIENTED_EDGE('',*,*,#65,.F.);
#981=CARTESIAN_POINT('',(-1.90895061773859,-26.932432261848,21.));
#982=DIRECTION('',(0.,0.,1.));
#983=DIRECTION('',(-1.,0.,0.));
#984=AXIS2_PLACEMENT_3D('',#981,#982,#983);
#985=CIRCLE('',#984,4.5);
#986=CARTESIAN_POINT('',(-5.66026089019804,-29.417924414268,21.));
#987=VERTEX_POINT('',#986);
#988=EDGE_CURVE('E504',#62,#987,#985,.F.);
#989=ORIENTED_EDGE('',*,*,#988,.T.);
#990=CARTESIAN_POINT('',(-24.,-41.569219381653,21.));
#991=DIRECTION('',(0.,0.,1.));
#992=DIRECTION('',(-1.,0.,0.));
#993=AXIS2_PLACEMENT_3D('',#990,#991,#992);
#994=CIRCLE('',#993,22.);
#995=CARTESIAN_POINT('',(-22.6465394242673,-19.610891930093,21.));
#996=VERTEX_POINT('',#995);
#997=EDGE_CURVE('E502',#996,#987,#994,.F.);
#998=ORIENTED_EDGE('',*,*,#997,.F.);
#999=CARTESIAN_POINT('',(-22.3696952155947,-15.1194158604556,21.));
#1000=DIRECTION('',(0.,0.,1.));
#1001=DIRECTION('',(-1.,0.,0.));
#1002=AXIS2_PLACEMENT_3D('',#999,#1000,#1001);
#1003=CIRCLE('',#1002,4.5);
#1004=EDGE_CURVE('E499',#996,#91,#1003,.F.);
#1005=ORIENTED_EDGE('',*,*,#1004,.T.);
#1006=ORIENTED_EDGE('',*,*,#92,.F.);
#1007=CARTESIAN_POINT('',(-24.2786458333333,-11.8130164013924,21.));
#1008=DIRECTION('',(0.,0.,1.));
#1009=DIRECTION('',(-1.,0.,0.));
#1010=AXIS2_PLACEMENT_3D('',#1007,#1008,#1009);
#1011=CIRCLE('',#1010,4.5);
#1012=CARTESIAN_POINT('',(-28.3068003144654,-9.807032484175,21.));
#1013=VERTEX_POINT('',#1012);
#1014=EDGE_CURVE('E496',#89,#1013,#1011,.F.);
#1015=ORIENTED_EDGE('',*,*,#1014,.T.);
#1016=CARTESIAN_POINT('',(-48.,0.,21.));
#1017=DIRECTION('',(0.,0.,1.));
#1018=DIRECTION('',(-1.,0.,0.));
#1019=AXIS2_PLACEMENT_3D('',#1016,#1017,#1018);
#1020=CIRCLE('',#1019,22.);
#1021=CARTESIAN_POINT('',(-28.3068003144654,9.80703248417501,21.));
#1022=VERTEX_POINT('',#1021);
#1023=EDGE_CURVE('E494',#1022,#1013,#1020,.F.);
#1024=ORIENTED_EDGE('',*,*,#1023,.F.);
#1025=CARTESIAN_POINT('',(-24.2786458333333,11.8130164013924,21.));
#1026=DIRECTION('',(0.,0.,1.));
#1027=DIRECTION('',(-1.,0.,0.));
#1028=AXIS2_PLACEMENT_3D('',#1025,#1026,#1027);
#1029=CIRCLE('',#1028,4.5);
#1030=EDGE_CURVE('E492',#1022,#118,#1029,.F.);
#1031=ORIENTED_EDGE('',*,*,#1030,.T.);
#1032=ORIENTED_EDGE('',*,*,#119,.F.);
#1033=CARTESIAN_POINT('',(-22.3696952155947,15.1194158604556,21.));
#1034=DIRECTION('',(0.,0.,1.));
#1035=DIRECTION('',(-1.,0.,0.));
#1036=AXIS2_PLACEMENT_3D('',#1033,#1034,#1035);
#1037=CIRCLE('',#1036,4.5);
#1038=CARTESIAN_POINT('',(-22.6465394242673,19.610891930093,21.));
#1039=VERTEX_POINT('',#1038);
#1040=EDGE_CURVE('E489',#116,#1039,#1037,.F.);
#1041=ORIENTED_EDGE('',*,*,#1040,.T.);
#1042=CARTESIAN_POINT('',(-24.,41.569219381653,21.));
#1043=DIRECTION('',(0.,0.,1.));
#1044=DIRECTION('',(-1.,0.,0.));
#1045=AXIS2_PLACEMENT_3D('',#1042,#1043,#1044);
#1046=CIRCLE('',#1045,22.);
#1047=CARTESIAN_POINT('',(-5.66026089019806,29.4179244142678,21.));
#1048=VERTEX_POINT('',#1047);
#1049=EDGE_CURVE('E487',#1048,#1039,#1046,.F.);
#1050=ORIENTED_EDGE('',*,*,#1049,.F.);
#1051=CARTESIAN_POINT('',(-1.90895061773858,26.932432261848,21.));
#1052=DIRECTION('',(0.,0.,1.));
#1053=DIRECTION('',(-1.,0.,0.));
#1054=AXIS2_PLACEMENT_3D('',#1051,#1052,#1053);
#1055=CIRCLE('',#1054,4.5);
#1056=EDGE_CURVE('E484',#1048,#145,#1055,.F.);
#1057=ORIENTED_EDGE('',*,*,#1056,.T.);
#1058=ORIENTED_EDGE('',*,*,#146,.F.);
#1059=CARTESIAN_POINT('',(1.90895061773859,26.932432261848,21.));
#1060=DIRECTION('',(0.,0.,1.));
#1061=DIRECTION('',(-1.,0.,0.));
#1062=AXIS2_PLACEMENT_3D('',#1059,#1060,#1061);
#1063=CIRCLE('',#1062,4.5);
#1064=CARTESIAN_POINT('',(5.66026089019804,29.4179244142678,21.));
#1065=VERTEX_POINT('',#1064);
#1066=EDGE_CURVE('E481',#143,#1065,#1063,.F.);
#1067=ORIENTED_EDGE('',*,*,#1066,.T.);
#1068=CARTESIAN_POINT('',(24.,41.569219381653,21.));
#1069=DIRECTION('',(0.,0.,1.));
#1070=DIRECTION('',(-1.,0.,0.));
#1071=AXIS2_PLACEMENT_3D('',#1068,#1069,#1070);
#1072=CIRCLE('',#1071,22.);
#1073=CARTESIAN_POINT('',(22.6465394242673,19.610891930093,21.));
#1074=VERTEX_POINT('',#1073);
#1075=EDGE_CURVE('E479',#1074,#1065,#1072,.F.);
#1076=ORIENTED_EDGE('',*,*,#1075,.F.);
#1077=CARTESIAN_POINT('',(22.3696952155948,15.1194158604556,21.));
#1078=DIRECTION('',(0.,0.,1.));
#1079=DIRECTION('',(-1.,0.,0.));
#1080=AXIS2_PLACEMENT_3D('',#1077,#1078,#1079);
#1081=CIRCLE('',#1080,4.5);
#1082=EDGE_CURVE('E477',#1074,#172,#1081,.F.);
#1083=ORIENTED_EDGE('',*,*,#1082,.T.);
#1084=ORIENTED_EDGE('',*,*,#173,.F.);
#1085=CARTESIAN_POINT('',(24.2786458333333,11.8130164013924,21.));
#1086=DIRECTION('',(0.,0.,1.));
#1087=DIRECTION('',(-1.,0.,0.));
#1088=AXIS2_PLACEMENT_3D('',#1085,#1086,#1087);
#1089=CIRCLE('',#1088,4.5);
#1090=CARTESIAN_POINT('',(28.3068003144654,9.80703248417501,21.));
#1091=VERTEX_POINT('',#1090);
#1092=EDGE_CURVE('E474',#170,#1091,#1089,.F.);
#1093=ORIENTED_EDGE('',*,*,#1092,.T.);
#1094=CARTESIAN_POINT('',(48.,0.,21.));
#1095=DIRECTION('',(0.,0.,1.));
#1096=DIRECTION('',(-1.,0.,0.));
#1097=AXIS2_PLACEMENT_3D('',#1094,#1095,#1096);
#1098=CIRCLE('',#1097,22.);
#1099=CARTESIAN_POINT('',(28.3068003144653,-9.8070324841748,21.));
#1100=VERTEX_POINT('',#1099);
#1101=EDGE_CURVE('E472',#1100,#1091,#1098,.F.);
#1102=ORIENTED_EDGE('',*,*,#1101,.F.);
#1103=CARTESIAN_POINT('',(24.2786458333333,-11.8130164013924,21.));
#1104=DIRECTION('',(0.,0.,1.));
#1105=DIRECTION('',(-1.,0.,0.));
#1106=AXIS2_PLACEMENT_3D('',#1103,#1104,#1105);
#1107=CIRCLE('',#1106,4.5);
#1108=EDGE_CURVE('E189',#1100,#32,#1107,.F.);
#1109=ORIENTED_EDGE('',*,*,#1108,.T.);
#1110=EDGE_LOOP('',(#954,#963,#972,#979,#980,#989,#998,#1005,#1006,#1015,#1024,#1031,#1032,
#1041,#1050,#1057,#1058,#1067,#1076,#1083,#1084,#1093,#1102,#1109));
#1111=FACE_BOUND('',#1110,.T.);
#1112=ORIENTED_EDGE('',*,*,#208,.T.);
#1113=EDGE_LOOP('',(#1112));
#1114=FACE_BOUND('',#1113,.T.);
#1115=ADVANCED_FACE('F399',(#1111,#1114),#953,.F.);
#1116=CARTESIAN_POINT('',(0.,0.,39.));
#1117=DIRECTION('',(0.,0.,1.));
#1118=DIRECTION('',(-1.,0.,0.));
#1119=AXIS2_PLACEMENT_3D('',#1116,#1117,#1118);
#1120=CYLINDRICAL_SURFACE('',#1119,16.);
#1121=CARTESIAN_POINT('',(0.,0.,39.));
#1122=DIRECTION('',(0.,0.,1.));
#1123=DIRECTION('',(-1.,0.,0.));
#1124=AXIS2_PLACEMENT_3D('',#1121,#1122,#1123);
#1125=CIRCLE('',#1124,16.);
#1126=CARTESIAN_POINT('',(-16.,0.,39.));
#1127=VERTEX_POINT('',#1126);
#1128=EDGE_CURVE('E202',#1127,#1127,#1125,.T.);
#1129=ORIENTED_EDGE('',*,*,#1128,.F.);
#1130=EDGE_LOOP('',(#1129));
#1131=FACE_BOUND('',#1130,.T.);
#1132=ORIENTED_EDGE('',*,*,#321,.T.);
#1133=EDGE_LOOP('',(#1132));
#1134=FACE_BOUND('',#1133,.T.);
#1135=ADVANCED_FACE('F231',(#1131,#1134),#1120,.F.);
#1136=CARTESIAN_POINT('',(0.,0.,39.));
#1137=DIRECTION('',(0.,0.,1.));
#1138=DIRECTION('',(-1.,0.,0.));
#1139=AXIS2_PLACEMENT_3D('',#1136,#1137,#1138);
#1140=PLANE('',#1139);
#1141=ORIENTED_EDGE('',*,*,#1128,.T.);
#1142=EDGE_LOOP('',(#1141));
#1143=FACE_BOUND('',#1142,.T.);
#1144=ADVANCED_FACE('F230',(#1143),#1140,.T.);
#1145=CARTESIAN_POINT('',(48.,0.,0.));
#1146=DIRECTION('',(0.,0.,1.));
#1147=DIRECTION('',(-1.,0.,0.));
#1148=AXIS2_PLACEMENT_3D('',#1145,#1146,#1147);
#1149=CYLINDRICAL_SURFACE('',#1148,22.);
#1150=DIRECTION('',(0.,0.,1.));
#1151=VECTOR('',#1150,1.);
#1152=CARTESIAN_POINT('',(28.3068003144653,-9.8070324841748,0.));
#1153=LINE('',#1152,#1151);
#1154=EDGE_CURVE('E29',#1100,#375,#1153,.T.);
#1155=ORIENTED_EDGE('',*,*,#1154,.F.);
#1156=ORIENTED_EDGE('',*,*,#1101,.T.);
#1157=DIRECTION('',(0.,0.,1.));
#1158=VECTOR('',#1157,1.);
#1159=CARTESIAN_POINT('',(28.3068003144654,9.80703248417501,0.));
#1160=LINE('',#1159,#1158);
#1161=EDGE_CURVE('E177',#1091,#432,#1160,.T.);
#1162=ORIENTED_EDGE('',*,*,#1161,.T.);
#1163=ORIENTED_EDGE('',*,*,#433,.F.);
#1164=EDGE_LOOP('',(#1155,#1156,#1162,#1163));
#1165=FACE_BOUND('',#1164,.T.);
#1166=ADVANCED_FACE('F175',(#1165),#1149,.F.);
#1167=CARTESIAN_POINT('',(24.2786458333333,11.8130164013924,0.));
#1168=DIRECTION('',(0.,0.,1.));
#1169=DIRECTION('',(-1.,0.,0.));
#1170=AXIS2_PLACEMENT_3D('',#1167,#1168,#1169);
#1171=CYLINDRICAL_SURFACE('',#1170,4.5);
#1172=ORIENTED_EDGE('',*,*,#454,.T.);
#1173=ORIENTED_EDGE('',*,*,#1161,.F.);
#1174=ORIENTED_EDGE('',*,*,#1092,.F.);
#1175=ORIENTED_EDGE('',*,*,#191,.T.);
#1176=EDGE_LOOP('',(#1172,#1173,#1174,#1175));
#1177=FACE_BOUND('',#1176,.T.);
#1178=ADVANCED_FACE('F226',(#1177),#1171,.T.);
#1179=CARTESIAN_POINT('',(24.2786458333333,-11.8130164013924,0.));
#1180=DIRECTION('',(0.,0.,1.));
#1181=DIRECTION('',(-1.,0.,0.));
#1182=AXIS2_PLACEMENT_3D('',#1179,#1180,#1181);
#1183=CYLINDRICAL_SURFACE('',#1182,4.5);
#1184=ORIENTED_EDGE('',*,*,#376,.T.);
#1185=ORIENTED_EDGE('',*,*,#41,.F.);
#1186=ORIENTED_EDGE('',*,*,#1108,.F.);
#1187=ORIENTED_EDGE('',*,*,#1154,.T.);
#1188=EDGE_LOOP('',(#1184,#1185,#1186,#1187));
#1189=FACE_BOUND('',#1188,.T.);
#1190=ADVANCED_FACE('F185',(#1189),#1183,.T.);
#1191=CARTESIAN_POINT('',(22.3696952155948,15.1194158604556,0.));
#1192=DIRECTION('',(0.,0.,1.));
#1193=DIRECTION('',(-1.,0.,0.));
#1194=AXIS2_PLACEMENT_3D('',#1191,#1192,#1193);
#1195=CYLINDRICAL_SURFACE('',#1194,4.5);
#1196=ORIENTED_EDGE('',*,*,#478,.T.);
#1197=ORIENTED_EDGE('',*,*,#181,.F.);
#1198=ORIENTED_EDGE('',*,*,#1082,.F.);
#1199=DIRECTION('',(0.,0.,1.));
#1200=VECTOR('',#1199,1.);
#1201=CARTESIAN_POINT('',(22.6465394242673,19.610891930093,0.));
#1202=LINE('',#1201,#1200);
#1203=EDGE_CURVE('E563',#1074,#477,#1202,.T.);
#1204=ORIENTED_EDGE('',*,*,#1203,.T.);
#1205=EDGE_LOOP('',(#1196,#1197,#1198,#1204));
#1206=FACE_BOUND('',#1205,.T.);
#1207=ADVANCED_FACE('F225',(#1206),#1195,.T.);
#1208=CARTESIAN_POINT('',(24.,41.569219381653,0.));
#1209=DIRECTION('',(0.,0.,1.));
#1210=DIRECTION('',(-1.,0.,0.));
#1211=AXIS2_PLACEMENT_3D('',#1208,#1209,#1210);
#1212=CYLINDRICAL_SURFACE('',#1211,22.);
#1213=ORIENTED_EDGE('',*,*,#1203,.F.);
#1214=ORIENTED_EDGE('',*,*,#1075,.T.);
#1215=DIRECTION('',(0.,0.,1.));
#1216=VECTOR('',#1215,1.);
#1217=CARTESIAN_POINT('',(5.66026089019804,29.4179244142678,0.));
#1218=LINE('',#1217,#1216);
#1219=EDGE_CURVE('E560',#1065,#534,#1218,.T.);
#1220=ORIENTED_EDGE('',*,*,#1219,.T.);
#1221=ORIENTED_EDGE('',*,*,#535,.F.);
#1222=EDGE_LOOP('',(#1213,#1214,#1220,#1221));
#1223=FACE_BOUND('',#1222,.T.);
#1224=ADVANCED_FACE('F261',(#1223),#1212,.F.);
#1225=CARTESIAN_POINT('',(1.90895061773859,26.932432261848,0.));
#1226=DIRECTION('',(0.,0.,1.));
#1227=DIRECTION('',(-1.,0.,0.));
#1228=AXIS2_PLACEMENT_3D('',#1225,#1226,#1227);
#1229=CYLINDRICAL_SURFACE('',#1228,4.5);
#1230=ORIENTED_EDGE('',*,*,#556,.T.);
#1231=ORIENTED_EDGE('',*,*,#1219,.F.);
#1232=ORIENTED_EDGE('',*,*,#1066,.F.);
#1233=ORIENTED_EDGE('',*,*,#164,.T.);
#1234=EDGE_LOOP('',(#1230,#1231,#1232,#1233));
#1235=FACE_BOUND('',#1234,.T.);
#1236=ADVANCED_FACE('F266',(#1235),#1229,.T.);
#1237=CARTESIAN_POINT('',(-1.90895061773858,26.932432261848,0.));
#1238=DIRECTION('',(0.,0.,1.));
#1239=DIRECTION('',(-1.,0.,0.));
#1240=AXIS2_PLACEMENT_3D('',#1237,#1238,#1239);
#1241=CYLINDRICAL_SURFACE('',#1240,4.5);
#1242=ORIENTED_EDGE('',*,*,#580,.T.);
#1243=ORIENTED_EDGE('',*,*,#154,.F.);
#1244=ORIENTED_EDGE('',*,*,#1056,.F.);
#1245=DIRECTION('',(0.,0.,1.));
#1246=VECTOR('',#1245,1.);
#1247=CARTESIAN_POINT('',(-5.66026089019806,29.4179244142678,0.));
#1248=LINE('',#1247,#1246);
#1249=EDGE_CURVE('E552',#1048,#579,#1248,.T.);
#1250=ORIENTED_EDGE('',*,*,#1249,.T.);
#1251=EDGE_LOOP('',(#1242,#1243,#1244,#1250));
#1252=FACE_BOUND('',#1251,.T.);
#1253=ADVANCED_FACE('F271',(#1252),#1241,.T.);
#1254=CARTESIAN_POINT('',(-24.,41.569219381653,0.));
#1255=DIRECTION('',(0.,0.,1.));
#1256=DIRECTION('',(-1.,0.,0.));
#1257=AXIS2_PLACEMENT_3D('',#1254,#1255,#1256);
#1258=CYLINDRICAL_SURFACE('',#1257,22.);
#1259=ORIENTED_EDGE('',*,*,#1249,.F.);
#1260=ORIENTED_EDGE('',*,*,#1049,.T.);
#1261=DIRECTION('',(0.,0.,1.));
#1262=VECTOR('',#1261,1.);
#1263=CARTESIAN_POINT('',(-22.6465394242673,19.610891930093,0.));
#1264=LINE('',#1263,#1262);
#1265=EDGE_CURVE('E549',#1039,#636,#1264,.T.);
#1266=ORIENTED_EDGE('',*,*,#1265,.T.);
#1267=ORIENTED_EDGE('',*,*,#637,.F.);
#1268=EDGE_LOOP('',(#1259,#1260,#1266,#1267));
#1269=FACE_BOUND('',#1268,.T.);
#1270=ADVANCED_FACE('F301',(#1269),#1258,.F.);
#1271=CARTESIAN_POINT('',(-22.3696952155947,15.1194158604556,0.));
#1272=DIRECTION('',(0.,0.,1.));
#1273=DIRECTION('',(-1.,0.,0.));
#1274=AXIS2_PLACEMENT_3D('',#1271,#1272,#1273);
#1275=CYLINDRICAL_SURFACE('',#1274,4.5);
#1276=ORIENTED_EDGE('',*,*,#658,.T.);
#1277=ORIENTED_EDGE('',*,*,#1265,.F.);
#1278=ORIENTED_EDGE('',*,*,#1040,.F.);
#1279=ORIENTED_EDGE('',*,*,#137,.T.);
#1280=EDGE_LOOP('',(#1276,#1277,#1278,#1279));
#1281=FACE_BOUND('',#1280,.T.);
#1282=ADVANCED_FACE('F304',(#1281),#1275,.T.);
#1283=CARTESIAN_POINT('',(-24.2786458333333,11.8130164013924,0.));
#1284=DIRECTION('',(0.,0.,1.));
#1285=DIRECTION('',(-1.,0.,0.));
#1286=AXIS2_PLACEMENT_3D('',#1283,#1284,#1285);
#1287=CYLINDRICAL_SURFACE('',#1286,4.5);
#1288=ORIENTED_EDGE('',*,*,#682,.T.);
#1289=ORIENTED_EDGE('',*,*,#127,.F.);
#1290=ORIENTED_EDGE('',*,*,#1030,.F.);
#1291=DIRECTION('',(0.,0.,1.));
#1292=VECTOR('',#1291,1.);
#1293=CARTESIAN_POINT('',(-28.3068003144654,9.80703248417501,0.));
#1294=LINE('',#1293,#1292);
#1295=EDGE_CURVE('E543',#1022,#681,#1294,.T.);
#1296=ORIENTED_EDGE('',*,*,#1295,.T.);
#1297=EDGE_LOOP('',(#1288,#1289,#1290,#1296));
#1298=FACE_BOUND('',#1297,.T.);
#1299=ADVANCED_FACE('F309',(#1298),#1287,.T.);
#1300=CARTESIAN_POINT('',(-48.,0.,0.));
#1301=DIRECTION('',(0.,0.,1.));
#1302=DIRECTION('',(-1.,0.,0.));
#1303=AXIS2_PLACEMENT_3D('',#1300,#1301,#1302);
#1304=CYLINDRICAL_SURFACE('',#1303,22.);
#1305=ORIENTED_EDGE('',*,*,#1295,.F.);
#1306=ORIENTED_EDGE('',*,*,#1023,.T.);
#1307=DIRECTION('',(0.,0.,1.));
#1308=VECTOR('',#1307,1.);
#1309=CARTESIAN_POINT('',(-28.3068003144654,-9.807032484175,0.));
#1310=LINE('',#1309,#1308);
#1311=EDGE_CURVE('E540',#1013,#738,#1310,.T.);
#1312=ORIENTED_EDGE('',*,*,#1311,.T.);
#1313=ORIENTED_EDGE('',*,*,#739,.F.);
#1314=EDGE_LOOP('',(#1305,#1306,#1312,#1313));
#1315=FACE_BOUND('',#1314,.T.);
#1316=ADVANCED_FACE('F314',(#1315),#1304,.F.);
#1317=CARTESIAN_POINT('',(-24.2786458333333,-11.8130164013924,0.));
#1318=DIRECTION('',(0.,0.,1.));
#1319=DIRECTION('',(-1.,0.,0.));
#1320=AXIS2_PLACEMENT_3D('',#1317,#1318,#1319);
#1321=CYLINDRICAL_SURFACE('',#1320,4.5);
#1322=ORIENTED_EDGE('',*,*,#760,.T.);
#1323=ORIENTED_EDGE('',*,*,#1311,.F.);
#1324=ORIENTED_EDGE('',*,*,#1014,.F.);
#1325=ORIENTED_EDGE('',*,*,#110,.T.);
#1326=EDGE_LOOP('',(#1322,#1323,#1324,#1325));
#1327=FACE_BOUND('',#1326,.T.);
#1328=ADVANCED_FACE('F343',(#1327),#1321,.T.);
#1329=CARTESIAN_POINT('',(-22.3696952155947,-15.1194158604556,0.));
#1330=DIRECTION('',(0.,0.,1.));
#1331=DIRECTION('',(-1.,0.,0.));
#1332=AXIS2_PLACEMENT_3D('',#1329,#1330,#1331);
#1333=CYLINDRICAL_SURFACE('',#1332,4.5);
#1334=ORIENTED_EDGE('',*,*,#784,.T.);
#1335=ORIENTED_EDGE('',*,*,#100,.F.);
#1336=ORIENTED_EDGE('',*,*,#1004,.F.);
#1337=DIRECTION('',(0.,0.,1.));
#1338=VECTOR('',#1337,1.);
#1339=CARTESIAN_POINT('',(-22.6465394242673,-19.610891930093,0.));
#1340=LINE('',#1339,#1338);
#1341=EDGE_CURVE('E532',#996,#783,#1340,.T.);
#1342=ORIENTED_EDGE('',*,*,#1341,.T.);
#1343=EDGE_LOOP('',(#1334,#1335,#1336,#1342));
#1344=FACE_BOUND('',#1343,.T.);
#1345=ADVANCED_FACE('F346',(#1344),#1333,.T.);
#1346=CARTESIAN_POINT('',(-24.,-41.569219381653,0.));
#1347=DIRECTION('',(0.,0.,1.));
#1348=DIRECTION('',(-1.,0.,0.));
#1349=AXIS2_PLACEMENT_3D('',#1346,#1347,#1348);
#1350=CYLINDRICAL_SURFACE('',#1349,22.);
#1351=ORIENTED_EDGE('',*,*,#1341,.F.);
#1352=ORIENTED_EDGE('',*,*,#997,.T.);
#1353=DIRECTION('',(0.,0.,1.));
#1354=VECTOR('',#1353,1.);
#1355=CARTESIAN_POINT('',(-5.66026089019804,-29.417924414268,0.));
#1356=LINE('',#1355,#1354);
#1357=EDGE_CURVE('E529',#987,#840,#1356,.T.);
#1358=ORIENTED_EDGE('',*,*,#1357,.T.);
#1359=ORIENTED_EDGE('',*,*,#841,.F.);
#1360=EDGE_LOOP('',(#1351,#1352,#1358,#1359));
#1361=FACE_BOUND('',#1360,.T.);
#1362=ADVANCED_FACE('F351',(#1361),#1350,.F.);
#1363=CARTESIAN_POINT('',(-1.90895061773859,-26.932432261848,0.));
#1364=DIRECTION('',(0.,0.,1.));
#1365=DIRECTION('',(-1.,0.,0.));
#1366=AXIS2_PLACEMENT_3D('',#1363,#1364,#1365);
#1367=CYLINDRICAL_SURFACE('',#1366,4.5);
#1368=ORIENTED_EDGE('',*,*,#862,.T.);
#1369=ORIENTED_EDGE('',*,*,#1357,.F.);
#1370=ORIENTED_EDGE('',*,*,#988,.F.);
#1371=ORIENTED_EDGE('',*,*,#83,.T.);
#1372=EDGE_LOOP('',(#1368,#1369,#1370,#1371));
#1373=FACE_BOUND('',#1372,.T.);
#1374=ADVANCED_FACE('F356',(#1373),#1367,.T.);
#1375=CARTESIAN_POINT('',(22.3696952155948,-15.1194158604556,0.));
#1376=DIRECTION('',(0.,0.,1.));
#1377=DIRECTION('',(-1.,0.,0.));
#1378=AXIS2_PLACEMENT_3D('',#1375,#1376,#1377);
#1379=CYLINDRICAL_SURFACE('',#1378,4.5);
#1380=ORIENTED_EDGE('',*,*,#352,.T.);
#1381=DIRECTION('',(0.,0.,1.));
#1382=VECTOR('',#1381,1.);
#1383=CARTESIAN_POINT('',(22.6465394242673,-19.610891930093,0.));
#1384=LINE('',#1383,#1382);
#1385=EDGE_CURVE('E513',#961,#351,#1384,.T.);
#1386=ORIENTED_EDGE('',*,*,#1385,.F.);
#1387=ORIENTED_EDGE('',*,*,#962,.F.);
#1388=ORIENTED_EDGE('',*,*,#56,.T.);
#1389=EDGE_LOOP('',(#1380,#1386,#1387,#1388));
#1390=FACE_BOUND('',#1389,.T.);
#1391=ADVANCED_FACE('F390',(#1390),#1379,.T.);
#1392=CARTESIAN_POINT('',(24.,-41.569219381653,0.));
#1393=DIRECTION('',(0.,0.,1.));
#1394=DIRECTION('',(-1.,0.,0.));
#1395=AXIS2_PLACEMENT_3D('',#1392,#1393,#1394);
#1396=CYLINDRICAL_SURFACE('',#1395,22.);
#1397=DIRECTION('',(0.,0.,1.));
#1398=VECTOR('',#1397,1.);
#1399=CARTESIAN_POINT('',(5.66026089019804,-29.417924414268,0.));
#1400=LINE('',#1399,#1398);
#1401=EDGE_CURVE('E516',#970,#885,#1400,.T.);
#1402=ORIENTED_EDGE('',*,*,#1401,.F.);
#1403=ORIENTED_EDGE('',*,*,#971,.T.);
#1404=ORIENTED_EDGE('',*,*,#1385,.T.);
#1405=ORIENTED_EDGE('',*,*,#941,.F.);
#1406=EDGE_LOOP('',(#1402,#1403,#1404,#1405));
#1407=FACE_BOUND('',#1406,.T.);
#1408=ADVANCED_FACE('F386',(#1407),#1396,.F.);
#1409=CARTESIAN_POINT('',(1.90895061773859,-26.932432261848,0.));
#1410=DIRECTION('',(0.,0.,1.));
#1411=DIRECTION('',(-1.,0.,0.));
#1412=AXIS2_PLACEMENT_3D('',#1409,#1410,#1411);
#1413=CYLINDRICAL_SURFACE('',#1412,4.5);
#1414=ORIENTED_EDGE('',*,*,#886,.T.);
#1415=ORIENTED_EDGE('',*,*,#73,.F.);
#1416=ORIENTED_EDGE('',*,*,#978,.F.);
#1417=ORIENTED_EDGE('',*,*,#1401,.T.);
#1418=EDGE_LOOP('',(#1414,#1415,#1416,#1417));
#1419=FACE_BOUND('',#1418,.T.);
#1420=ADVANCED_FACE('F383',(#1419),#1413,.T.);
#1421=CLOSED_SHELL('',(#60,#87,#114,#141,#168,#195,#223,#243,#263,#283,#292,#325,#948,#1115,
#1135,#1144,#1166,#1178,#1190,#1207,#1224,#1236,#1253,#1270,#1282,#1299,#1316,#1328,#1345,#1362,
#1374,#1391,#1408,#1420));
#1422=MANIFOLD_SOLID_BREP('B1',#1421);
#1423=ADVANCED_BREP_SHAPE_REPRESENTATION('',(#18,#1422),#14);
#1424=SHAPE_DEFINITION_REPRESENTATION(#9,#1423);
ENDSEC;
END-ISO-10303-21;
